VERSION 5.7 ;
  NOWIREEXTENSIONATPIN ON ;
  DIVIDERCHAR "/" ;
  BUSBITCHARS "[]" ;
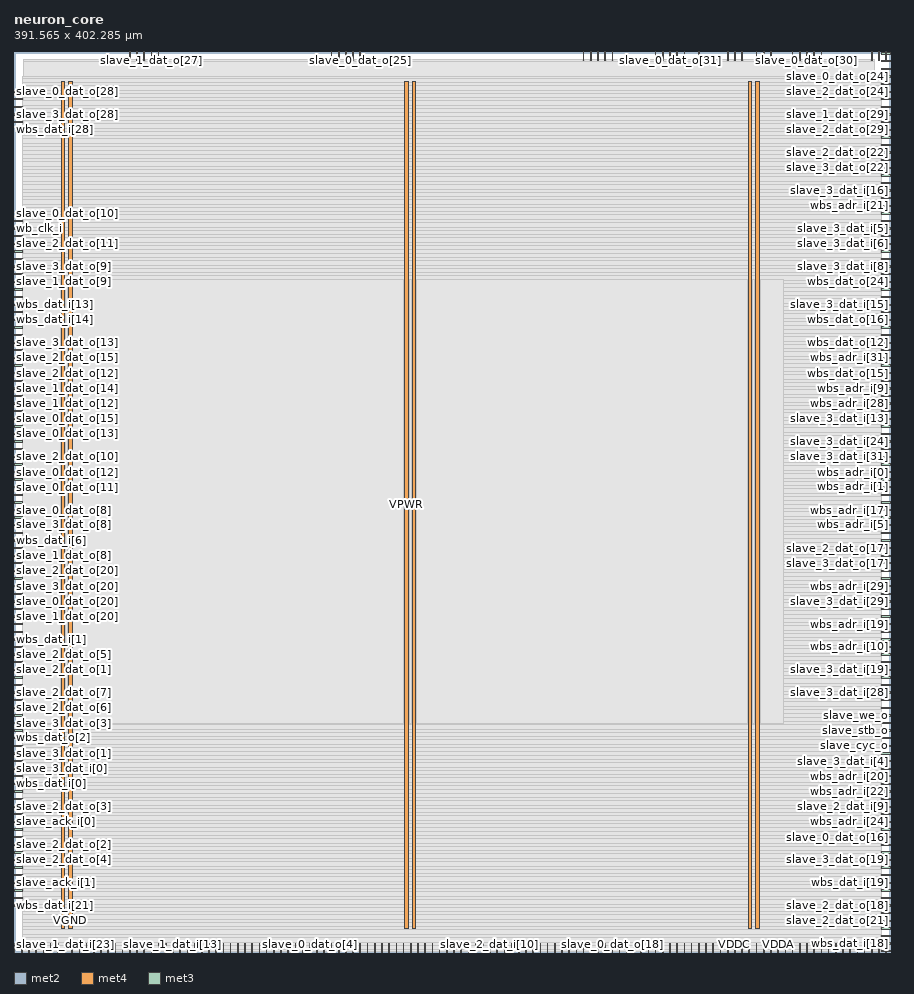
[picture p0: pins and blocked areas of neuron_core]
MACRO neuron_core
  CLASS BLOCK ;
  FOREIGN neuron_core ;
  ORIGIN 0.000 0.000 ;
  SIZE 391.565 BY 402.285 ;
  PIN VDDA
    DIRECTION INOUT ;
    USE SIGNAL ;
    PORT
      LAYER met2 ;
        RECT 341.410 0.000 341.690 4.000 ;
    END
  END VDDA
  PIN VDDC
    DIRECTION INOUT ;
    USE SIGNAL ;
    PORT
      LAYER met2 ;
        RECT 322.090 0.000 322.370 4.000 ;
    END
  END VDDC
  PIN VGND
    DIRECTION INOUT ;
    USE GROUND ;
    PORT
      LAYER met4 ;
        RECT 24.340 10.640 25.940 389.200 ;
    END
    PORT
      LAYER met4 ;
        RECT 177.940 10.640 179.540 389.200 ;
    END
    PORT
      LAYER met4 ;
        RECT 331.540 10.640 333.140 389.200 ;
    END
  END VGND
  PIN VPWR
    DIRECTION INOUT ;
    USE POWER ;
    PORT
      LAYER met4 ;
        RECT 21.040 10.640 22.640 389.200 ;
    END
    PORT
      LAYER met4 ;
        RECT 174.640 10.640 176.240 389.200 ;
    END
    PORT
      LAYER met4 ;
        RECT 328.240 10.640 329.840 389.200 ;
    END
  END VPWR
  PIN VSS
    DIRECTION INOUT ;
    USE SIGNAL ;
    PORT
      LAYER met2 ;
        RECT 19.410 0.000 19.690 4.000 ;
    END
  END VSS
  PIN slave_0_dat_i[0]
    DIRECTION INPUT ;
    USE SIGNAL ;
    ANTENNAGATEAREA 0.631200 ;
    ANTENNADIFFAREA 0.434700 ;
    PORT
      LAYER met2 ;
        RECT 167.530 0.000 167.810 4.000 ;
    END
  END slave_0_dat_i[0]
  PIN slave_0_dat_i[10]
    DIRECTION INPUT ;
    USE SIGNAL ;
    PORT
      LAYER met2 ;
        RECT 312.430 0.000 312.710 4.000 ;
    END
  END slave_0_dat_i[10]
  PIN slave_0_dat_i[11]
    DIRECTION INPUT ;
    USE SIGNAL ;
    PORT
      LAYER met2 ;
        RECT 22.630 0.000 22.910 4.000 ;
    END
  END slave_0_dat_i[11]
  PIN slave_0_dat_i[12]
    DIRECTION INPUT ;
    USE SIGNAL ;
    PORT
      LAYER met2 ;
        RECT 74.150 0.000 74.430 4.000 ;
    END
  END slave_0_dat_i[12]
  PIN slave_0_dat_i[13]
    DIRECTION INPUT ;
    USE SIGNAL ;
    PORT
      LAYER met2 ;
        RECT 389.710 0.000 389.990 4.000 ;
    END
  END slave_0_dat_i[13]
  PIN slave_0_dat_i[14]
    DIRECTION INPUT ;
    USE SIGNAL ;
    PORT
      LAYER met2 ;
        RECT 54.830 0.000 55.110 4.000 ;
    END
  END slave_0_dat_i[14]
  PIN slave_0_dat_i[15]
    DIRECTION INPUT ;
    USE SIGNAL ;
    PORT
      LAYER met2 ;
        RECT 48.390 0.000 48.670 4.000 ;
    END
  END slave_0_dat_i[15]
  PIN slave_0_dat_i[16]
    DIRECTION INPUT ;
    USE SIGNAL ;
    PORT
      LAYER met2 ;
        RECT 96.690 0.000 96.970 4.000 ;
    END
  END slave_0_dat_i[16]
  PIN slave_0_dat_i[17]
    DIRECTION INPUT ;
    USE SIGNAL ;
    PORT
      LAYER met2 ;
        RECT 87.030 0.000 87.310 4.000 ;
    END
  END slave_0_dat_i[17]
  PIN slave_0_dat_i[18]
    DIRECTION INPUT ;
    USE SIGNAL ;
    PORT
      LAYER met2 ;
        RECT 64.490 0.000 64.770 4.000 ;
    END
  END slave_0_dat_i[18]
  PIN slave_0_dat_i[19]
    DIRECTION INPUT ;
    USE SIGNAL ;
    PORT
      LAYER met2 ;
        RECT 58.050 0.000 58.330 4.000 ;
    END
  END slave_0_dat_i[19]
  PIN slave_0_dat_i[1]
    DIRECTION INPUT ;
    USE SIGNAL ;
    PORT
      LAYER met2 ;
        RECT 45.170 0.000 45.450 4.000 ;
    END
  END slave_0_dat_i[1]
  PIN slave_0_dat_i[20]
    DIRECTION INPUT ;
    USE SIGNAL ;
    PORT
      LAYER met2 ;
        RECT 386.490 0.000 386.770 4.000 ;
    END
  END slave_0_dat_i[20]
  PIN slave_0_dat_i[21]
    DIRECTION INPUT ;
    USE SIGNAL ;
    PORT
      LAYER met2 ;
        RECT 51.610 0.000 51.890 4.000 ;
    END
  END slave_0_dat_i[21]
  PIN slave_0_dat_i[22]
    DIRECTION INPUT ;
    USE SIGNAL ;
    PORT
      LAYER met2 ;
        RECT 80.590 0.000 80.870 4.000 ;
    END
  END slave_0_dat_i[22]
  PIN slave_0_dat_i[23]
    DIRECTION INPUT ;
    USE SIGNAL ;
    PORT
      LAYER met2 ;
        RECT 9.750 0.000 10.030 4.000 ;
    END
  END slave_0_dat_i[23]
  PIN slave_0_dat_i[24]
    DIRECTION INPUT ;
    USE SIGNAL ;
    PORT
      LAYER met2 ;
        RECT 183.630 0.000 183.910 4.000 ;
    END
  END slave_0_dat_i[24]
  PIN slave_0_dat_i[25]
    DIRECTION INPUT ;
    USE SIGNAL ;
    PORT
      LAYER met2 ;
        RECT 83.810 0.000 84.090 4.000 ;
    END
  END slave_0_dat_i[25]
  PIN slave_0_dat_i[26]
    DIRECTION INPUT ;
    USE SIGNAL ;
    PORT
      LAYER met2 ;
        RECT 103.130 0.000 103.410 4.000 ;
    END
  END slave_0_dat_i[26]
  PIN slave_0_dat_i[27]
    DIRECTION INPUT ;
    USE SIGNAL ;
    PORT
      LAYER met2 ;
        RECT 370.390 0.000 370.670 4.000 ;
    END
  END slave_0_dat_i[27]
  PIN slave_0_dat_i[28]
    DIRECTION INPUT ;
    USE SIGNAL ;
    PORT
      LAYER met2 ;
        RECT 206.170 0.000 206.450 4.000 ;
    END
  END slave_0_dat_i[28]
  PIN slave_0_dat_i[29]
    DIRECTION INPUT ;
    USE SIGNAL ;
    PORT
      LAYER met2 ;
        RECT 225.490 0.000 225.770 4.000 ;
    END
  END slave_0_dat_i[29]
  PIN slave_0_dat_i[2]
    DIRECTION INPUT ;
    USE SIGNAL ;
    PORT
      LAYER met2 ;
        RECT 90.250 0.000 90.530 4.000 ;
    END
  END slave_0_dat_i[2]
  PIN slave_0_dat_i[30]
    DIRECTION INPUT ;
    USE SIGNAL ;
    PORT
      LAYER met2 ;
        RECT 12.970 0.000 13.250 4.000 ;
    END
  END slave_0_dat_i[30]
  PIN slave_0_dat_i[31]
    DIRECTION INPUT ;
    USE SIGNAL ;
    PORT
      LAYER met2 ;
        RECT 93.470 0.000 93.750 4.000 ;
    END
  END slave_0_dat_i[31]
  PIN slave_0_dat_i[3]
    DIRECTION INPUT ;
    USE SIGNAL ;
    PORT
      LAYER met2 ;
        RECT 106.350 0.000 106.630 4.000 ;
    END
  END slave_0_dat_i[3]
  PIN slave_0_dat_i[4]
    DIRECTION INPUT ;
    USE SIGNAL ;
    PORT
      LAYER met2 ;
        RECT 347.850 0.000 348.130 4.000 ;
    END
  END slave_0_dat_i[4]
  PIN slave_0_dat_i[5]
    DIRECTION INPUT ;
    USE SIGNAL ;
    PORT
      LAYER met2 ;
        RECT 202.950 0.000 203.230 4.000 ;
    END
  END slave_0_dat_i[5]
  PIN slave_0_dat_i[6]
    DIRECTION INPUT ;
    USE SIGNAL ;
    PORT
      LAYER met2 ;
        RECT 99.910 0.000 100.190 4.000 ;
    END
  END slave_0_dat_i[6]
  PIN slave_0_dat_i[7]
    DIRECTION INPUT ;
    USE SIGNAL ;
    PORT
      LAYER met2 ;
        RECT 41.950 0.000 42.230 4.000 ;
    END
  END slave_0_dat_i[7]
  PIN slave_0_dat_i[8]
    DIRECTION INPUT ;
    USE SIGNAL ;
    PORT
      LAYER met2 ;
        RECT 190.070 0.000 190.350 4.000 ;
    END
  END slave_0_dat_i[8]
  PIN slave_0_dat_i[9]
    DIRECTION INPUT ;
    USE SIGNAL ;
    PORT
      LAYER met2 ;
        RECT 3.310 0.000 3.590 4.000 ;
    END
  END slave_0_dat_i[9]
  PIN slave_0_dat_o[0]
    DIRECTION OUTPUT ;
    USE SIGNAL ;
    ANTENNADIFFAREA 0.445500 ;
    PORT
      LAYER met2 ;
        RECT 109.570 0.000 109.850 4.000 ;
    END
  END slave_0_dat_o[0]
  PIN slave_0_dat_o[10]
    DIRECTION OUTPUT ;
    USE SIGNAL ;
    ANTENNADIFFAREA 0.445500 ;
    PORT
      LAYER met3 ;
        RECT 0.000 326.440 4.000 327.040 ;
    END
  END slave_0_dat_o[10]
  PIN slave_0_dat_o[11]
    DIRECTION OUTPUT ;
    USE SIGNAL ;
    ANTENNADIFFAREA 0.445500 ;
    PORT
      LAYER met3 ;
        RECT 0.000 207.440 4.000 208.040 ;
    END
  END slave_0_dat_o[11]
  PIN slave_0_dat_o[12]
    DIRECTION OUTPUT ;
    USE SIGNAL ;
    ANTENNADIFFAREA 0.445500 ;
    PORT
      LAYER met3 ;
        RECT 0.000 214.240 4.000 214.840 ;
    END
  END slave_0_dat_o[12]
  PIN slave_0_dat_o[13]
    DIRECTION OUTPUT ;
    USE SIGNAL ;
    ANTENNADIFFAREA 0.445500 ;
    PORT
      LAYER met3 ;
        RECT 0.000 231.240 4.000 231.840 ;
    END
  END slave_0_dat_o[13]
  PIN slave_0_dat_o[14]
    DIRECTION OUTPUT ;
    USE SIGNAL ;
    ANTENNADIFFAREA 0.445500 ;
    PORT
      LAYER met3 ;
        RECT 0.000 234.640 4.000 235.240 ;
    END
  END slave_0_dat_o[14]
  PIN slave_0_dat_o[15]
    DIRECTION OUTPUT ;
    USE SIGNAL ;
    ANTENNADIFFAREA 0.445500 ;
    PORT
      LAYER met3 ;
        RECT 0.000 238.040 4.000 238.640 ;
    END
  END slave_0_dat_o[15]
  PIN slave_0_dat_o[16]
    DIRECTION OUTPUT ;
    USE SIGNAL ;
    ANTENNADIFFAREA 0.445500 ;
    PORT
      LAYER met3 ;
        RECT 387.565 51.040 391.565 51.640 ;
    END
  END slave_0_dat_o[16]
  PIN slave_0_dat_o[17]
    DIRECTION OUTPUT ;
    USE SIGNAL ;
    ANTENNADIFFAREA 0.445500 ;
    PORT
      LAYER met3 ;
        RECT 387.565 166.640 391.565 167.240 ;
    END
  END slave_0_dat_o[17]
  PIN slave_0_dat_o[18]
    DIRECTION OUTPUT ;
    USE SIGNAL ;
    ANTENNADIFFAREA 0.445500 ;
    PORT
      LAYER met2 ;
        RECT 267.350 0.000 267.630 4.000 ;
    END
  END slave_0_dat_o[18]
  PIN slave_0_dat_o[19]
    DIRECTION OUTPUT ;
    USE SIGNAL ;
    ANTENNADIFFAREA 0.445500 ;
    PORT
      LAYER met2 ;
        RECT 357.510 0.000 357.790 4.000 ;
    END
  END slave_0_dat_o[19]
  PIN slave_0_dat_o[1]
    DIRECTION OUTPUT ;
    USE SIGNAL ;
    ANTENNADIFFAREA 0.445500 ;
    PORT
      LAYER met2 ;
        RECT 116.010 0.000 116.290 4.000 ;
    END
  END slave_0_dat_o[1]
  PIN slave_0_dat_o[20]
    DIRECTION OUTPUT ;
    USE SIGNAL ;
    ANTENNADIFFAREA 0.445500 ;
    PORT
      LAYER met3 ;
        RECT 0.000 156.440 4.000 157.040 ;
    END
  END slave_0_dat_o[20]
  PIN slave_0_dat_o[21]
    DIRECTION OUTPUT ;
    USE SIGNAL ;
    ANTENNADIFFAREA 0.445500 ;
    PORT
      LAYER met2 ;
        RECT 193.290 0.000 193.570 4.000 ;
    END
  END slave_0_dat_o[21]
  PIN slave_0_dat_o[22]
    DIRECTION OUTPUT ;
    USE SIGNAL ;
    ANTENNADIFFAREA 0.445500 ;
    PORT
      LAYER met3 ;
        RECT 387.565 343.440 391.565 344.040 ;
    END
  END slave_0_dat_o[22]
  PIN slave_0_dat_o[23]
    DIRECTION OUTPUT ;
    USE SIGNAL ;
    ANTENNADIFFAREA 0.445500 ;
    PORT
      LAYER met2 ;
        RECT 254.470 398.285 254.750 402.285 ;
    END
  END slave_0_dat_o[23]
  PIN slave_0_dat_o[24]
    DIRECTION OUTPUT ;
    USE SIGNAL ;
    ANTENNADIFFAREA 0.445500 ;
    PORT
      LAYER met3 ;
        RECT 387.565 391.040 391.565 391.640 ;
    END
  END slave_0_dat_o[24]
  PIN slave_0_dat_o[25]
    DIRECTION OUTPUT ;
    USE SIGNAL ;
    ANTENNADIFFAREA 0.445500 ;
    PORT
      LAYER met2 ;
        RECT 154.650 398.285 154.930 402.285 ;
    END
  END slave_0_dat_o[25]
  PIN slave_0_dat_o[26]
    DIRECTION OUTPUT ;
    USE SIGNAL ;
    ANTENNADIFFAREA 0.445500 ;
    PORT
      LAYER met2 ;
        RECT 293.110 0.000 293.390 4.000 ;
    END
  END slave_0_dat_o[26]
  PIN slave_0_dat_o[27]
    DIRECTION OUTPUT ;
    USE SIGNAL ;
    ANTENNADIFFAREA 0.445500 ;
    PORT
      LAYER met2 ;
        RECT 51.610 398.285 51.890 402.285 ;
    END
  END slave_0_dat_o[27]
  PIN slave_0_dat_o[28]
    DIRECTION OUTPUT ;
    USE SIGNAL ;
    ANTENNADIFFAREA 0.445500 ;
    PORT
      LAYER met3 ;
        RECT 0.000 384.240 4.000 384.840 ;
    END
  END slave_0_dat_o[28]
  PIN slave_0_dat_o[29]
    DIRECTION OUTPUT ;
    USE SIGNAL ;
    ANTENNADIFFAREA 0.445500 ;
    PORT
      LAYER met3 ;
        RECT 387.565 363.840 391.565 364.440 ;
    END
  END slave_0_dat_o[29]
  PIN slave_0_dat_o[2]
    DIRECTION OUTPUT ;
    USE SIGNAL ;
    ANTENNADIFFAREA 0.445500 ;
    PORT
      LAYER met2 ;
        RECT 119.230 0.000 119.510 4.000 ;
    END
  END slave_0_dat_o[2]
  PIN slave_0_dat_o[30]
    DIRECTION OUTPUT ;
    USE SIGNAL ;
    ANTENNADIFFAREA 0.445500 ;
    PORT
      LAYER met2 ;
        RECT 354.290 398.285 354.570 402.285 ;
    END
  END slave_0_dat_o[30]
  PIN slave_0_dat_o[31]
    DIRECTION OUTPUT ;
    USE SIGNAL ;
    ANTENNADIFFAREA 0.445500 ;
    PORT
      LAYER met2 ;
        RECT 293.110 398.285 293.390 402.285 ;
    END
  END slave_0_dat_o[31]
  PIN slave_0_dat_o[3]
    DIRECTION OUTPUT ;
    USE SIGNAL ;
    ANTENNADIFFAREA 0.445500 ;
    PORT
      LAYER met2 ;
        RECT 125.670 0.000 125.950 4.000 ;
    END
  END slave_0_dat_o[3]
  PIN slave_0_dat_o[4]
    DIRECTION OUTPUT ;
    USE SIGNAL ;
    ANTENNADIFFAREA 0.445500 ;
    PORT
      LAYER met2 ;
        RECT 132.110 0.000 132.390 4.000 ;
    END
  END slave_0_dat_o[4]
  PIN slave_0_dat_o[5]
    DIRECTION OUTPUT ;
    USE SIGNAL ;
    ANTENNADIFFAREA 0.445500 ;
    PORT
      LAYER met2 ;
        RECT 128.890 0.000 129.170 4.000 ;
    END
  END slave_0_dat_o[5]
  PIN slave_0_dat_o[6]
    DIRECTION OUTPUT ;
    USE SIGNAL ;
    ANTENNADIFFAREA 0.445500 ;
    PORT
      LAYER met2 ;
        RECT 122.450 0.000 122.730 4.000 ;
    END
  END slave_0_dat_o[6]
  PIN slave_0_dat_o[7]
    DIRECTION OUTPUT ;
    USE SIGNAL ;
    ANTENNADIFFAREA 0.445500 ;
    PORT
      LAYER met2 ;
        RECT 112.790 0.000 113.070 4.000 ;
    END
  END slave_0_dat_o[7]
  PIN slave_0_dat_o[8]
    DIRECTION OUTPUT ;
    USE SIGNAL ;
    ANTENNADIFFAREA 0.445500 ;
    PORT
      LAYER met3 ;
        RECT 0.000 197.240 4.000 197.840 ;
    END
  END slave_0_dat_o[8]
  PIN slave_0_dat_o[9]
    DIRECTION OUTPUT ;
    USE SIGNAL ;
    ANTENNADIFFAREA 0.445500 ;
    PORT
      LAYER met3 ;
        RECT 0.000 295.840 4.000 296.440 ;
    END
  END slave_0_dat_o[9]
  PIN slave_1_dat_i[0]
    DIRECTION INPUT ;
    USE SIGNAL ;
    ANTENNAGATEAREA 0.631200 ;
    ANTENNADIFFAREA 0.434700 ;
    PORT
      LAYER met2 ;
        RECT 173.970 0.000 174.250 4.000 ;
    END
  END slave_1_dat_i[0]
  PIN slave_1_dat_i[10]
    DIRECTION INPUT ;
    USE SIGNAL ;
    PORT
      LAYER met2 ;
        RECT 180.410 0.000 180.690 4.000 ;
    END
  END slave_1_dat_i[10]
  PIN slave_1_dat_i[11]
    DIRECTION INPUT ;
    USE SIGNAL ;
    PORT
      LAYER met2 ;
        RECT 6.530 0.000 6.810 4.000 ;
    END
  END slave_1_dat_i[11]
  PIN slave_1_dat_i[12]
    DIRECTION INPUT ;
    USE SIGNAL ;
    PORT
      LAYER met2 ;
        RECT 222.270 0.000 222.550 4.000 ;
    END
  END slave_1_dat_i[12]
  PIN slave_1_dat_i[13]
    DIRECTION INPUT ;
    USE SIGNAL ;
    PORT
      LAYER met2 ;
        RECT 70.930 0.000 71.210 4.000 ;
    END
  END slave_1_dat_i[13]
  PIN slave_1_dat_i[14]
    DIRECTION INPUT ;
    USE SIGNAL ;
    PORT
      LAYER met2 ;
        RECT 228.710 0.000 228.990 4.000 ;
    END
  END slave_1_dat_i[14]
  PIN slave_1_dat_i[15]
    DIRECTION INPUT ;
    USE SIGNAL ;
    PORT
      LAYER met2 ;
        RECT 35.510 0.000 35.790 4.000 ;
    END
  END slave_1_dat_i[15]
  PIN slave_1_dat_i[16]
    DIRECTION INPUT ;
    USE SIGNAL ;
    PORT
      LAYER met2 ;
        RECT 383.270 0.000 383.550 4.000 ;
    END
  END slave_1_dat_i[16]
  PIN slave_1_dat_i[17]
    DIRECTION INPUT ;
    USE SIGNAL ;
    PORT
      LAYER met2 ;
        RECT 25.850 0.000 26.130 4.000 ;
    END
  END slave_1_dat_i[17]
  PIN slave_1_dat_i[18]
    DIRECTION INPUT ;
    USE SIGNAL ;
    PORT
      LAYER met2 ;
        RECT 67.710 0.000 67.990 4.000 ;
    END
  END slave_1_dat_i[18]
  PIN slave_1_dat_i[19]
    DIRECTION INPUT ;
    USE SIGNAL ;
    PORT
      LAYER met2 ;
        RECT 161.090 0.000 161.370 4.000 ;
    END
  END slave_1_dat_i[19]
  PIN slave_1_dat_i[1]
    DIRECTION INPUT ;
    USE SIGNAL ;
    PORT
      LAYER met2 ;
        RECT 186.850 0.000 187.130 4.000 ;
    END
  END slave_1_dat_i[1]
  PIN slave_1_dat_i[20]
    DIRECTION INPUT ;
    USE SIGNAL ;
    PORT
      LAYER met2 ;
        RECT 373.610 0.000 373.890 4.000 ;
    END
  END slave_1_dat_i[20]
  PIN slave_1_dat_i[21]
    DIRECTION INPUT ;
    USE SIGNAL ;
    PORT
      LAYER met2 ;
        RECT 215.830 0.000 216.110 4.000 ;
    END
  END slave_1_dat_i[21]
  PIN slave_1_dat_i[22]
    DIRECTION INPUT ;
    USE SIGNAL ;
    PORT
      LAYER met2 ;
        RECT 32.290 0.000 32.570 4.000 ;
    END
  END slave_1_dat_i[22]
  PIN slave_1_dat_i[23]
    DIRECTION INPUT ;
    USE SIGNAL ;
    PORT
      LAYER met2 ;
        RECT 16.190 0.000 16.470 4.000 ;
    END
  END slave_1_dat_i[23]
  PIN slave_1_dat_i[24]
    DIRECTION INPUT ;
    USE SIGNAL ;
    PORT
      LAYER met2 ;
        RECT 231.930 0.000 232.210 4.000 ;
    END
  END slave_1_dat_i[24]
  PIN slave_1_dat_i[25]
    DIRECTION INPUT ;
    USE SIGNAL ;
    PORT
      LAYER met2 ;
        RECT 164.310 0.000 164.590 4.000 ;
    END
  END slave_1_dat_i[25]
  PIN slave_1_dat_i[26]
    DIRECTION INPUT ;
    USE SIGNAL ;
    PORT
      LAYER met2 ;
        RECT 0.090 0.000 0.370 4.000 ;
    END
  END slave_1_dat_i[26]
  PIN slave_1_dat_i[27]
    DIRECTION INPUT ;
    USE SIGNAL ;
    PORT
      LAYER met2 ;
        RECT 38.730 0.000 39.010 4.000 ;
    END
  END slave_1_dat_i[27]
  PIN slave_1_dat_i[28]
    DIRECTION INPUT ;
    USE SIGNAL ;
    PORT
      LAYER met2 ;
        RECT 61.270 0.000 61.550 4.000 ;
    END
  END slave_1_dat_i[28]
  PIN slave_1_dat_i[29]
    DIRECTION INPUT ;
    USE SIGNAL ;
    PORT
      LAYER met2 ;
        RECT 177.190 0.000 177.470 4.000 ;
    END
  END slave_1_dat_i[29]
  PIN slave_1_dat_i[2]
    DIRECTION INPUT ;
    USE SIGNAL ;
    PORT
      LAYER met2 ;
        RECT 286.670 0.000 286.950 4.000 ;
    END
  END slave_1_dat_i[2]
  PIN slave_1_dat_i[30]
    DIRECTION INPUT ;
    USE SIGNAL ;
    PORT
      LAYER met2 ;
        RECT 305.990 0.000 306.270 4.000 ;
    END
  END slave_1_dat_i[30]
  PIN slave_1_dat_i[31]
    DIRECTION INPUT ;
    USE SIGNAL ;
    PORT
      LAYER met2 ;
        RECT 257.690 0.000 257.970 4.000 ;
    END
  END slave_1_dat_i[31]
  PIN slave_1_dat_i[3]
    DIRECTION INPUT ;
    USE SIGNAL ;
    PORT
      LAYER met2 ;
        RECT 277.010 0.000 277.290 4.000 ;
    END
  END slave_1_dat_i[3]
  PIN slave_1_dat_i[4]
    DIRECTION INPUT ;
    USE SIGNAL ;
    PORT
      LAYER met2 ;
        RECT 29.070 0.000 29.350 4.000 ;
    END
  END slave_1_dat_i[4]
  PIN slave_1_dat_i[5]
    DIRECTION INPUT ;
    USE SIGNAL ;
    PORT
      LAYER met2 ;
        RECT 77.370 0.000 77.650 4.000 ;
    END
  END slave_1_dat_i[5]
  PIN slave_1_dat_i[6]
    DIRECTION INPUT ;
    USE SIGNAL ;
    PORT
      LAYER met2 ;
        RECT 199.730 0.000 200.010 4.000 ;
    END
  END slave_1_dat_i[6]
  PIN slave_1_dat_i[7]
    DIRECTION INPUT ;
    USE SIGNAL ;
    PORT
      LAYER met2 ;
        RECT 354.290 0.000 354.570 4.000 ;
    END
  END slave_1_dat_i[7]
  PIN slave_1_dat_i[8]
    DIRECTION INPUT ;
    USE SIGNAL ;
    PORT
      LAYER met2 ;
        RECT 344.630 0.000 344.910 4.000 ;
    END
  END slave_1_dat_i[8]
  PIN slave_1_dat_i[9]
    DIRECTION INPUT ;
    USE SIGNAL ;
    PORT
      LAYER met2 ;
        RECT 209.390 0.000 209.670 4.000 ;
    END
  END slave_1_dat_i[9]
  PIN slave_1_dat_o[0]
    DIRECTION OUTPUT ;
    USE SIGNAL ;
    ANTENNADIFFAREA 0.445500 ;
    PORT
      LAYER met2 ;
        RECT 157.870 0.000 158.150 4.000 ;
    END
  END slave_1_dat_o[0]
  PIN slave_1_dat_o[10]
    DIRECTION OUTPUT ;
    USE SIGNAL ;
    ANTENNADIFFAREA 0.445500 ;
    PORT
      LAYER met3 ;
        RECT 0.000 217.640 4.000 218.240 ;
    END
  END slave_1_dat_o[10]
  PIN slave_1_dat_o[11]
    DIRECTION OUTPUT ;
    USE SIGNAL ;
    ANTENNADIFFAREA 0.445500 ;
    PORT
      LAYER met3 ;
        RECT 0.000 312.840 4.000 313.440 ;
    END
  END slave_1_dat_o[11]
  PIN slave_1_dat_o[12]
    DIRECTION OUTPUT ;
    USE SIGNAL ;
    ANTENNADIFFAREA 0.445500 ;
    PORT
      LAYER met3 ;
        RECT 0.000 241.440 4.000 242.040 ;
    END
  END slave_1_dat_o[12]
  PIN slave_1_dat_o[13]
    DIRECTION OUTPUT ;
    USE SIGNAL ;
    ANTENNADIFFAREA 0.445500 ;
    PORT
      LAYER met3 ;
        RECT 0.000 244.840 4.000 245.440 ;
    END
  END slave_1_dat_o[13]
  PIN slave_1_dat_o[14]
    DIRECTION OUTPUT ;
    USE SIGNAL ;
    ANTENNADIFFAREA 0.445500 ;
    PORT
      LAYER met3 ;
        RECT 0.000 248.240 4.000 248.840 ;
    END
  END slave_1_dat_o[14]
  PIN slave_1_dat_o[15]
    DIRECTION OUTPUT ;
    USE SIGNAL ;
    ANTENNADIFFAREA 0.445500 ;
    PORT
      LAYER met3 ;
        RECT 0.000 251.640 4.000 252.240 ;
    END
  END slave_1_dat_o[15]
  PIN slave_1_dat_o[16]
    DIRECTION OUTPUT ;
    USE SIGNAL ;
    ANTENNADIFFAREA 0.445500 ;
    PORT
      LAYER met3 ;
        RECT 387.565 34.040 391.565 34.640 ;
    END
  END slave_1_dat_o[16]
  PIN slave_1_dat_o[17]
    DIRECTION OUTPUT ;
    USE SIGNAL ;
    ANTENNADIFFAREA 0.445500 ;
    PORT
      LAYER met3 ;
        RECT 387.565 183.640 391.565 184.240 ;
    END
  END slave_1_dat_o[17]
  PIN slave_1_dat_o[18]
    DIRECTION OUTPUT ;
    USE SIGNAL ;
    ANTENNADIFFAREA 0.445500 ;
    PORT
      LAYER met2 ;
        RECT 270.570 0.000 270.850 4.000 ;
    END
  END slave_1_dat_o[18]
  PIN slave_1_dat_o[19]
    DIRECTION OUTPUT ;
    USE SIGNAL ;
    ANTENNADIFFAREA 0.445500 ;
    PORT
      LAYER met2 ;
        RECT 360.730 0.000 361.010 4.000 ;
    END
  END slave_1_dat_o[19]
  PIN slave_1_dat_o[1]
    DIRECTION OUTPUT ;
    USE SIGNAL ;
    ANTENNADIFFAREA 0.445500 ;
    PORT
      LAYER met2 ;
        RECT 151.430 0.000 151.710 4.000 ;
    END
  END slave_1_dat_o[1]
  PIN slave_1_dat_o[20]
    DIRECTION OUTPUT ;
    USE SIGNAL ;
    ANTENNADIFFAREA 0.445500 ;
    PORT
      LAYER met3 ;
        RECT 0.000 153.040 4.000 153.640 ;
    END
  END slave_1_dat_o[20]
  PIN slave_1_dat_o[21]
    DIRECTION OUTPUT ;
    USE SIGNAL ;
    ANTENNADIFFAREA 0.445500 ;
    PORT
      LAYER met2 ;
        RECT 196.510 0.000 196.790 4.000 ;
    END
  END slave_1_dat_o[21]
  PIN slave_1_dat_o[22]
    DIRECTION OUTPUT ;
    USE SIGNAL ;
    ANTENNADIFFAREA 0.445500 ;
    PORT
      LAYER met3 ;
        RECT 387.565 353.640 391.565 354.240 ;
    END
  END slave_1_dat_o[22]
  PIN slave_1_dat_o[23]
    DIRECTION OUTPUT ;
    USE SIGNAL ;
    ANTENNADIFFAREA 0.445500 ;
    PORT
      LAYER met2 ;
        RECT 267.350 398.285 267.630 402.285 ;
    END
  END slave_1_dat_o[23]
  PIN slave_1_dat_o[24]
    DIRECTION OUTPUT ;
    USE SIGNAL ;
    ANTENNADIFFAREA 0.445500 ;
    PORT
      LAYER met3 ;
        RECT 387.565 380.840 391.565 381.440 ;
    END
  END slave_1_dat_o[24]
  PIN slave_1_dat_o[25]
    DIRECTION OUTPUT ;
    USE SIGNAL ;
    ANTENNADIFFAREA 0.445500 ;
    PORT
      LAYER met2 ;
        RECT 148.210 398.285 148.490 402.285 ;
    END
  END slave_1_dat_o[25]
  PIN slave_1_dat_o[26]
    DIRECTION OUTPUT ;
    USE SIGNAL ;
    ANTENNADIFFAREA 0.445500 ;
    PORT
      LAYER met2 ;
        RECT 296.330 0.000 296.610 4.000 ;
    END
  END slave_1_dat_o[26]
  PIN slave_1_dat_o[27]
    DIRECTION OUTPUT ;
    USE SIGNAL ;
    ANTENNADIFFAREA 0.445500 ;
    PORT
      LAYER met2 ;
        RECT 61.270 398.285 61.550 402.285 ;
    END
  END slave_1_dat_o[27]
  PIN slave_1_dat_o[28]
    DIRECTION OUTPUT ;
    USE SIGNAL ;
    ANTENNADIFFAREA 0.445500 ;
    PORT
      LAYER met3 ;
        RECT 0.000 377.440 4.000 378.040 ;
    END
  END slave_1_dat_o[28]
  PIN slave_1_dat_o[29]
    DIRECTION OUTPUT ;
    USE SIGNAL ;
    ANTENNADIFFAREA 0.445500 ;
    PORT
      LAYER met3 ;
        RECT 387.565 374.040 391.565 374.640 ;
    END
  END slave_1_dat_o[29]
  PIN slave_1_dat_o[2]
    DIRECTION OUTPUT ;
    USE SIGNAL ;
    ANTENNADIFFAREA 0.445500 ;
    PORT
      LAYER met2 ;
        RECT 141.770 0.000 142.050 4.000 ;
    END
  END slave_1_dat_o[2]
  PIN slave_1_dat_o[30]
    DIRECTION OUTPUT ;
    USE SIGNAL ;
    ANTENNADIFFAREA 0.445500 ;
    PORT
      LAYER met2 ;
        RECT 347.850 398.285 348.130 402.285 ;
    END
  END slave_1_dat_o[30]
  PIN slave_1_dat_o[31]
    DIRECTION OUTPUT ;
    USE SIGNAL ;
    ANTENNADIFFAREA 0.445500 ;
    PORT
      LAYER met2 ;
        RECT 286.670 398.285 286.950 402.285 ;
    END
  END slave_1_dat_o[31]
  PIN slave_1_dat_o[3]
    DIRECTION OUTPUT ;
    USE SIGNAL ;
    ANTENNADIFFAREA 0.445500 ;
    PORT
      LAYER met2 ;
        RECT 138.550 0.000 138.830 4.000 ;
    END
  END slave_1_dat_o[3]
  PIN slave_1_dat_o[4]
    DIRECTION OUTPUT ;
    USE SIGNAL ;
    ANTENNADIFFAREA 0.445500 ;
    PORT
      LAYER met2 ;
        RECT 144.990 0.000 145.270 4.000 ;
    END
  END slave_1_dat_o[4]
  PIN slave_1_dat_o[5]
    DIRECTION OUTPUT ;
    USE SIGNAL ;
    ANTENNADIFFAREA 0.445500 ;
    PORT
      LAYER met2 ;
        RECT 154.650 0.000 154.930 4.000 ;
    END
  END slave_1_dat_o[5]
  PIN slave_1_dat_o[6]
    DIRECTION OUTPUT ;
    USE SIGNAL ;
    ANTENNADIFFAREA 0.445500 ;
    PORT
      LAYER met2 ;
        RECT 148.210 0.000 148.490 4.000 ;
    END
  END slave_1_dat_o[6]
  PIN slave_1_dat_o[7]
    DIRECTION OUTPUT ;
    USE SIGNAL ;
    ANTENNADIFFAREA 0.445500 ;
    PORT
      LAYER met2 ;
        RECT 135.330 0.000 135.610 4.000 ;
    END
  END slave_1_dat_o[7]
  PIN slave_1_dat_o[8]
    DIRECTION OUTPUT ;
    USE SIGNAL ;
    ANTENNADIFFAREA 0.445500 ;
    PORT
      LAYER met3 ;
        RECT 0.000 176.840 4.000 177.440 ;
    END
  END slave_1_dat_o[8]
  PIN slave_1_dat_o[9]
    DIRECTION OUTPUT ;
    USE SIGNAL ;
    ANTENNADIFFAREA 0.445500 ;
    PORT
      LAYER met3 ;
        RECT 0.000 299.240 4.000 299.840 ;
    END
  END slave_1_dat_o[9]
  PIN slave_2_dat_i[0]
    DIRECTION INPUT ;
    USE SIGNAL ;
    ANTENNAGATEAREA 0.560700 ;
    ANTENNADIFFAREA 0.434700 ;
    PORT
      LAYER met2 ;
        RECT 170.750 0.000 171.030 4.000 ;
    END
  END slave_2_dat_i[0]
  PIN slave_2_dat_i[10]
    DIRECTION INPUT ;
    USE SIGNAL ;
    PORT
      LAYER met2 ;
        RECT 212.610 0.000 212.890 4.000 ;
    END
  END slave_2_dat_i[10]
  PIN slave_2_dat_i[11]
    DIRECTION INPUT ;
    USE SIGNAL ;
    PORT
      LAYER met2 ;
        RECT 273.790 0.000 274.070 4.000 ;
    END
  END slave_2_dat_i[11]
  PIN slave_2_dat_i[12]
    DIRECTION INPUT ;
    USE SIGNAL ;
    PORT
      LAYER met2 ;
        RECT 219.050 0.000 219.330 4.000 ;
    END
  END slave_2_dat_i[12]
  PIN slave_2_dat_i[13]
    DIRECTION INPUT ;
    USE SIGNAL ;
    PORT
      LAYER met2 ;
        RECT 315.650 0.000 315.930 4.000 ;
    END
  END slave_2_dat_i[13]
  PIN slave_2_dat_i[14]
    DIRECTION INPUT ;
    USE SIGNAL ;
    PORT
      LAYER met2 ;
        RECT 248.030 0.000 248.310 4.000 ;
    END
  END slave_2_dat_i[14]
  PIN slave_2_dat_i[15]
    DIRECTION INPUT ;
    USE SIGNAL ;
    PORT
      LAYER met2 ;
        RECT 338.190 0.000 338.470 4.000 ;
    END
  END slave_2_dat_i[15]
  PIN slave_2_dat_i[16]
    DIRECTION INPUT ;
    USE SIGNAL ;
    PORT
      LAYER met2 ;
        RECT 280.230 0.000 280.510 4.000 ;
    END
  END slave_2_dat_i[16]
  PIN slave_2_dat_i[17]
    DIRECTION INPUT ;
    USE SIGNAL ;
    PORT
      LAYER met2 ;
        RECT 235.150 0.000 235.430 4.000 ;
    END
  END slave_2_dat_i[17]
  PIN slave_2_dat_i[18]
    DIRECTION INPUT ;
    USE SIGNAL ;
    PORT
      LAYER met2 ;
        RECT 238.370 0.000 238.650 4.000 ;
    END
  END slave_2_dat_i[18]
  PIN slave_2_dat_i[19]
    DIRECTION INPUT ;
    USE SIGNAL ;
    PORT
      LAYER met2 ;
        RECT 241.590 0.000 241.870 4.000 ;
    END
  END slave_2_dat_i[19]
  PIN slave_2_dat_i[1]
    DIRECTION INPUT ;
    USE SIGNAL ;
    PORT
      LAYER met2 ;
        RECT 244.810 0.000 245.090 4.000 ;
    END
  END slave_2_dat_i[1]
  PIN slave_2_dat_i[20]
    DIRECTION INPUT ;
    USE SIGNAL ;
    PORT
      LAYER met2 ;
        RECT 367.170 0.000 367.450 4.000 ;
    END
  END slave_2_dat_i[20]
  PIN slave_2_dat_i[21]
    DIRECTION INPUT ;
    USE SIGNAL ;
    PORT
      LAYER met2 ;
        RECT 251.250 0.000 251.530 4.000 ;
    END
  END slave_2_dat_i[21]
  PIN slave_2_dat_i[22]
    DIRECTION INPUT ;
    USE SIGNAL ;
    PORT
      LAYER met2 ;
        RECT 254.470 0.000 254.750 4.000 ;
    END
  END slave_2_dat_i[22]
  PIN slave_2_dat_i[23]
    DIRECTION INPUT ;
    USE SIGNAL ;
    PORT
      LAYER met2 ;
        RECT 334.970 0.000 335.250 4.000 ;
    END
  END slave_2_dat_i[23]
  PIN slave_2_dat_i[24]
    DIRECTION INPUT ;
    USE SIGNAL ;
    PORT
      LAYER met2 ;
        RECT 260.910 0.000 261.190 4.000 ;
    END
  END slave_2_dat_i[24]
  PIN slave_2_dat_i[25]
    DIRECTION INPUT ;
    USE SIGNAL ;
    PORT
      LAYER met2 ;
        RECT 264.130 0.000 264.410 4.000 ;
    END
  END slave_2_dat_i[25]
  PIN slave_2_dat_i[26]
    DIRECTION INPUT ;
    USE SIGNAL ;
    PORT
      LAYER met2 ;
        RECT 331.750 0.000 332.030 4.000 ;
    END
  END slave_2_dat_i[26]
  PIN slave_2_dat_i[27]
    DIRECTION INPUT ;
    USE SIGNAL ;
    PORT
      LAYER met2 ;
        RECT 299.550 0.000 299.830 4.000 ;
    END
  END slave_2_dat_i[27]
  PIN slave_2_dat_i[28]
    DIRECTION INPUT ;
    USE SIGNAL ;
    PORT
      LAYER met2 ;
        RECT 283.450 0.000 283.730 4.000 ;
    END
  END slave_2_dat_i[28]
  PIN slave_2_dat_i[29]
    DIRECTION INPUT ;
    USE SIGNAL ;
    PORT
      LAYER met2 ;
        RECT 328.530 0.000 328.810 4.000 ;
    END
  END slave_2_dat_i[29]
  PIN slave_2_dat_i[2]
    DIRECTION INPUT ;
    USE SIGNAL ;
    PORT
      LAYER met2 ;
        RECT 363.950 0.000 364.230 4.000 ;
    END
  END slave_2_dat_i[2]
  PIN slave_2_dat_i[30]
    DIRECTION INPUT ;
    USE SIGNAL ;
    PORT
      LAYER met2 ;
        RECT 380.050 0.000 380.330 4.000 ;
    END
  END slave_2_dat_i[30]
  PIN slave_2_dat_i[31]
    DIRECTION INPUT ;
    USE SIGNAL ;
    PORT
      LAYER met2 ;
        RECT 376.830 0.000 377.110 4.000 ;
    END
  END slave_2_dat_i[31]
  PIN slave_2_dat_i[3]
    DIRECTION INPUT ;
    USE SIGNAL ;
    PORT
      LAYER met2 ;
        RECT 309.210 0.000 309.490 4.000 ;
    END
  END slave_2_dat_i[3]
  PIN slave_2_dat_i[4]
    DIRECTION INPUT ;
    USE SIGNAL ;
    PORT
      LAYER met2 ;
        RECT 289.890 0.000 290.170 4.000 ;
    END
  END slave_2_dat_i[4]
  PIN slave_2_dat_i[5]
    DIRECTION INPUT ;
    USE SIGNAL ;
    PORT
      LAYER met2 ;
        RECT 325.310 0.000 325.590 4.000 ;
    END
  END slave_2_dat_i[5]
  PIN slave_2_dat_i[6]
    DIRECTION INPUT ;
    USE SIGNAL ;
    PORT
      LAYER met2 ;
        RECT 318.870 0.000 319.150 4.000 ;
    END
  END slave_2_dat_i[6]
  PIN slave_2_dat_i[7]
    DIRECTION INPUT ;
    USE SIGNAL ;
    PORT
      LAYER met2 ;
        RECT 351.070 0.000 351.350 4.000 ;
    END
  END slave_2_dat_i[7]
  PIN slave_2_dat_i[8]
    DIRECTION INPUT ;
    USE SIGNAL ;
    PORT
      LAYER met2 ;
        RECT 302.770 0.000 303.050 4.000 ;
    END
  END slave_2_dat_i[8]
  PIN slave_2_dat_i[9]
    DIRECTION INPUT ;
    USE SIGNAL ;
    PORT
      LAYER met3 ;
        RECT 387.565 64.640 391.565 65.240 ;
    END
  END slave_2_dat_i[9]
  PIN slave_2_dat_o[0]
    DIRECTION OUTPUT ;
    USE SIGNAL ;
    ANTENNADIFFAREA 0.445500 ;
    PORT
      LAYER met3 ;
        RECT 0.000 23.840 4.000 24.440 ;
    END
  END slave_2_dat_o[0]
  PIN slave_2_dat_o[10]
    DIRECTION OUTPUT ;
    USE SIGNAL ;
    ANTENNADIFFAREA 0.445500 ;
    PORT
      LAYER met3 ;
        RECT 0.000 221.040 4.000 221.640 ;
    END
  END slave_2_dat_o[10]
  PIN slave_2_dat_o[11]
    DIRECTION OUTPUT ;
    USE SIGNAL ;
    ANTENNADIFFAREA 0.445500 ;
    PORT
      LAYER met3 ;
        RECT 0.000 316.240 4.000 316.840 ;
    END
  END slave_2_dat_o[11]
  PIN slave_2_dat_o[12]
    DIRECTION OUTPUT ;
    USE SIGNAL ;
    ANTENNADIFFAREA 0.445500 ;
    PORT
      LAYER met3 ;
        RECT 0.000 255.040 4.000 255.640 ;
    END
  END slave_2_dat_o[12]
  PIN slave_2_dat_o[13]
    DIRECTION OUTPUT ;
    USE SIGNAL ;
    ANTENNADIFFAREA 0.445500 ;
    PORT
      LAYER met3 ;
        RECT 0.000 258.440 4.000 259.040 ;
    END
  END slave_2_dat_o[13]
  PIN slave_2_dat_o[14]
    DIRECTION OUTPUT ;
    USE SIGNAL ;
    ANTENNADIFFAREA 0.445500 ;
    PORT
      LAYER met3 ;
        RECT 0.000 261.840 4.000 262.440 ;
    END
  END slave_2_dat_o[14]
  PIN slave_2_dat_o[15]
    DIRECTION OUTPUT ;
    USE SIGNAL ;
    ANTENNADIFFAREA 0.445500 ;
    PORT
      LAYER met3 ;
        RECT 0.000 265.240 4.000 265.840 ;
    END
  END slave_2_dat_o[15]
  PIN slave_2_dat_o[16]
    DIRECTION OUTPUT ;
    USE SIGNAL ;
    ANTENNADIFFAREA 0.445500 ;
    PORT
      LAYER met3 ;
        RECT 387.565 47.640 391.565 48.240 ;
    END
  END slave_2_dat_o[16]
  PIN slave_2_dat_o[17]
    DIRECTION OUTPUT ;
    USE SIGNAL ;
    ANTENNADIFFAREA 0.445500 ;
    PORT
      LAYER met3 ;
        RECT 387.565 180.240 391.565 180.840 ;
    END
  END slave_2_dat_o[17]
  PIN slave_2_dat_o[18]
    DIRECTION OUTPUT ;
    USE SIGNAL ;
    ANTENNADIFFAREA 0.445500 ;
    PORT
      LAYER met3 ;
        RECT 387.565 20.440 391.565 21.040 ;
    END
  END slave_2_dat_o[18]
  PIN slave_2_dat_o[19]
    DIRECTION OUTPUT ;
    USE SIGNAL ;
    ANTENNADIFFAREA 0.445500 ;
    PORT
      LAYER met3 ;
        RECT 387.565 27.240 391.565 27.840 ;
    END
  END slave_2_dat_o[19]
  PIN slave_2_dat_o[1]
    DIRECTION OUTPUT ;
    USE SIGNAL ;
    ANTENNADIFFAREA 0.445500 ;
    PORT
      LAYER met3 ;
        RECT 0.000 125.840 4.000 126.440 ;
    END
  END slave_2_dat_o[1]
  PIN slave_2_dat_o[20]
    DIRECTION OUTPUT ;
    USE SIGNAL ;
    ANTENNADIFFAREA 0.445500 ;
    PORT
      LAYER met3 ;
        RECT 0.000 170.040 4.000 170.640 ;
    END
  END slave_2_dat_o[20]
  PIN slave_2_dat_o[21]
    DIRECTION OUTPUT ;
    USE SIGNAL ;
    ANTENNADIFFAREA 0.445500 ;
    PORT
      LAYER met3 ;
        RECT 387.565 13.640 391.565 14.240 ;
    END
  END slave_2_dat_o[21]
  PIN slave_2_dat_o[22]
    DIRECTION OUTPUT ;
    USE SIGNAL ;
    ANTENNADIFFAREA 0.445500 ;
    PORT
      LAYER met3 ;
        RECT 387.565 357.040 391.565 357.640 ;
    END
  END slave_2_dat_o[22]
  PIN slave_2_dat_o[23]
    DIRECTION OUTPUT ;
    USE SIGNAL ;
    ANTENNADIFFAREA 0.445500 ;
    PORT
      LAYER met2 ;
        RECT 264.130 398.285 264.410 402.285 ;
    END
  END slave_2_dat_o[23]
  PIN slave_2_dat_o[24]
    DIRECTION OUTPUT ;
    USE SIGNAL ;
    ANTENNADIFFAREA 0.445500 ;
    PORT
      LAYER met3 ;
        RECT 387.565 384.240 391.565 384.840 ;
    END
  END slave_2_dat_o[24]
  PIN slave_2_dat_o[25]
    DIRECTION OUTPUT ;
    USE SIGNAL ;
    ANTENNADIFFAREA 0.445500 ;
    PORT
      LAYER met2 ;
        RECT 151.430 398.285 151.710 402.285 ;
    END
  END slave_2_dat_o[25]
  PIN slave_2_dat_o[26]
    DIRECTION OUTPUT ;
    USE SIGNAL ;
    ANTENNADIFFAREA 0.445500 ;
    PORT
      LAYER met3 ;
        RECT 387.565 17.040 391.565 17.640 ;
    END
  END slave_2_dat_o[26]
  PIN slave_2_dat_o[27]
    DIRECTION OUTPUT ;
    USE SIGNAL ;
    ANTENNADIFFAREA 0.445500 ;
    PORT
      LAYER met2 ;
        RECT 64.490 398.285 64.770 402.285 ;
    END
  END slave_2_dat_o[27]
  PIN slave_2_dat_o[28]
    DIRECTION OUTPUT ;
    USE SIGNAL ;
    ANTENNADIFFAREA 0.445500 ;
    PORT
      LAYER met3 ;
        RECT 0.000 380.840 4.000 381.440 ;
    END
  END slave_2_dat_o[28]
  PIN slave_2_dat_o[29]
    DIRECTION OUTPUT ;
    USE SIGNAL ;
    ANTENNADIFFAREA 0.445500 ;
    PORT
      LAYER met3 ;
        RECT 387.565 367.240 391.565 367.840 ;
    END
  END slave_2_dat_o[29]
  PIN slave_2_dat_o[2]
    DIRECTION OUTPUT ;
    USE SIGNAL ;
    ANTENNADIFFAREA 0.445500 ;
    PORT
      LAYER met3 ;
        RECT 0.000 47.640 4.000 48.240 ;
    END
  END slave_2_dat_o[2]
  PIN slave_2_dat_o[30]
    DIRECTION OUTPUT ;
    USE SIGNAL ;
    ANTENNADIFFAREA 0.445500 ;
    PORT
      LAYER met2 ;
        RECT 357.510 398.285 357.790 402.285 ;
    END
  END slave_2_dat_o[30]
  PIN slave_2_dat_o[31]
    DIRECTION OUTPUT ;
    USE SIGNAL ;
    ANTENNADIFFAREA 0.445500 ;
    PORT
      LAYER met2 ;
        RECT 296.330 398.285 296.610 402.285 ;
    END
  END slave_2_dat_o[31]
  PIN slave_2_dat_o[3]
    DIRECTION OUTPUT ;
    USE SIGNAL ;
    ANTENNADIFFAREA 0.445500 ;
    PORT
      LAYER met3 ;
        RECT 0.000 64.640 4.000 65.240 ;
    END
  END slave_2_dat_o[3]
  PIN slave_2_dat_o[4]
    DIRECTION OUTPUT ;
    USE SIGNAL ;
    ANTENNADIFFAREA 0.445500 ;
    PORT
      LAYER met3 ;
        RECT 0.000 40.840 4.000 41.440 ;
    END
  END slave_2_dat_o[4]
  PIN slave_2_dat_o[5]
    DIRECTION OUTPUT ;
    USE SIGNAL ;
    ANTENNADIFFAREA 0.445500 ;
    PORT
      LAYER met3 ;
        RECT 0.000 129.240 4.000 129.840 ;
    END
  END slave_2_dat_o[5]
  PIN slave_2_dat_o[6]
    DIRECTION OUTPUT ;
    USE SIGNAL ;
    ANTENNADIFFAREA 0.445500 ;
    PORT
      LAYER met3 ;
        RECT 0.000 108.840 4.000 109.440 ;
    END
  END slave_2_dat_o[6]
  PIN slave_2_dat_o[7]
    DIRECTION OUTPUT ;
    USE SIGNAL ;
    ANTENNADIFFAREA 0.445500 ;
    PORT
      LAYER met3 ;
        RECT 0.000 115.640 4.000 116.240 ;
    END
  END slave_2_dat_o[7]
  PIN slave_2_dat_o[8]
    DIRECTION OUTPUT ;
    USE SIGNAL ;
    ANTENNADIFFAREA 0.445500 ;
    PORT
      LAYER met3 ;
        RECT 0.000 200.640 4.000 201.240 ;
    END
  END slave_2_dat_o[8]
  PIN slave_2_dat_o[9]
    DIRECTION OUTPUT ;
    USE SIGNAL ;
    ANTENNADIFFAREA 0.445500 ;
    PORT
      LAYER met3 ;
        RECT 0.000 302.640 4.000 303.240 ;
    END
  END slave_2_dat_o[9]
  PIN slave_3_dat_i[0]
    DIRECTION INPUT ;
    USE SIGNAL ;
    ANTENNAGATEAREA 0.631200 ;
    ANTENNADIFFAREA 0.434700 ;
    PORT
      LAYER met3 ;
        RECT 0.000 81.640 4.000 82.240 ;
    END
  END slave_3_dat_i[0]
  PIN slave_3_dat_i[10]
    DIRECTION INPUT ;
    USE SIGNAL ;
    PORT
      LAYER met3 ;
        RECT 387.565 312.840 391.565 313.440 ;
    END
  END slave_3_dat_i[10]
  PIN slave_3_dat_i[11]
    DIRECTION INPUT ;
    USE SIGNAL ;
    PORT
      LAYER met3 ;
        RECT 387.565 278.840 391.565 279.440 ;
    END
  END slave_3_dat_i[11]
  PIN slave_3_dat_i[12]
    DIRECTION INPUT ;
    USE SIGNAL ;
    PORT
      LAYER met3 ;
        RECT 387.565 309.440 391.565 310.040 ;
    END
  END slave_3_dat_i[12]
  PIN slave_3_dat_i[13]
    DIRECTION INPUT ;
    USE SIGNAL ;
    PORT
      LAYER met3 ;
        RECT 387.565 238.040 391.565 238.640 ;
    END
  END slave_3_dat_i[13]
  PIN slave_3_dat_i[14]
    DIRECTION INPUT ;
    USE SIGNAL ;
    PORT
      LAYER met3 ;
        RECT 387.565 132.640 391.565 133.240 ;
    END
  END slave_3_dat_i[14]
  PIN slave_3_dat_i[15]
    DIRECTION INPUT ;
    USE SIGNAL ;
    PORT
      LAYER met3 ;
        RECT 387.565 289.040 391.565 289.640 ;
    END
  END slave_3_dat_i[15]
  PIN slave_3_dat_i[16]
    DIRECTION INPUT ;
    USE SIGNAL ;
    PORT
      LAYER met3 ;
        RECT 387.565 340.040 391.565 340.640 ;
    END
  END slave_3_dat_i[16]
  PIN slave_3_dat_i[17]
    DIRECTION INPUT ;
    USE SIGNAL ;
    PORT
      LAYER met3 ;
        RECT 387.565 78.240 391.565 78.840 ;
    END
  END slave_3_dat_i[17]
  PIN slave_3_dat_i[18]
    DIRECTION INPUT ;
    USE SIGNAL ;
    PORT
      LAYER met3 ;
        RECT 387.565 71.440 391.565 72.040 ;
    END
  END slave_3_dat_i[18]
  PIN slave_3_dat_i[19]
    DIRECTION INPUT ;
    USE SIGNAL ;
    PORT
      LAYER met3 ;
        RECT 387.565 125.840 391.565 126.440 ;
    END
  END slave_3_dat_i[19]
  PIN slave_3_dat_i[1]
    DIRECTION INPUT ;
    USE SIGNAL ;
    PORT
      LAYER met3 ;
        RECT 387.565 261.840 391.565 262.440 ;
    END
  END slave_3_dat_i[1]
  PIN slave_3_dat_i[20]
    DIRECTION INPUT ;
    USE SIGNAL ;
    PORT
      LAYER met3 ;
        RECT 387.565 122.440 391.565 123.040 ;
    END
  END slave_3_dat_i[20]
  PIN slave_3_dat_i[21]
    DIRECTION INPUT ;
    USE SIGNAL ;
    PORT
      LAYER met3 ;
        RECT 387.565 54.440 391.565 55.040 ;
    END
  END slave_3_dat_i[21]
  PIN slave_3_dat_i[22]
    DIRECTION INPUT ;
    USE SIGNAL ;
    PORT
      LAYER met3 ;
        RECT 387.565 326.440 391.565 327.040 ;
    END
  END slave_3_dat_i[22]
  PIN slave_3_dat_i[23]
    DIRECTION INPUT ;
    USE SIGNAL ;
    PORT
      LAYER met3 ;
        RECT 387.565 88.440 391.565 89.040 ;
    END
  END slave_3_dat_i[23]
  PIN slave_3_dat_i[24]
    DIRECTION INPUT ;
    USE SIGNAL ;
    PORT
      LAYER met3 ;
        RECT 387.565 227.840 391.565 228.440 ;
    END
  END slave_3_dat_i[24]
  PIN slave_3_dat_i[25]
    DIRECTION INPUT ;
    USE SIGNAL ;
    PORT
      LAYER met3 ;
        RECT 387.565 251.640 391.565 252.240 ;
    END
  END slave_3_dat_i[25]
  PIN slave_3_dat_i[26]
    DIRECTION INPUT ;
    USE SIGNAL ;
    PORT
      LAYER met3 ;
        RECT 387.565 61.240 391.565 61.840 ;
    END
  END slave_3_dat_i[26]
  PIN slave_3_dat_i[27]
    DIRECTION INPUT ;
    USE SIGNAL ;
    PORT
      LAYER met3 ;
        RECT 387.565 292.440 391.565 293.040 ;
    END
  END slave_3_dat_i[27]
  PIN slave_3_dat_i[28]
    DIRECTION INPUT ;
    USE SIGNAL ;
    PORT
      LAYER met3 ;
        RECT 387.565 115.640 391.565 116.240 ;
    END
  END slave_3_dat_i[28]
  PIN slave_3_dat_i[29]
    DIRECTION INPUT ;
    USE SIGNAL ;
    PORT
      LAYER met3 ;
        RECT 387.565 156.440 391.565 157.040 ;
    END
  END slave_3_dat_i[29]
  PIN slave_3_dat_i[2]
    DIRECTION INPUT ;
    USE SIGNAL ;
    PORT
      LAYER met3 ;
        RECT 387.565 285.640 391.565 286.240 ;
    END
  END slave_3_dat_i[2]
  PIN slave_3_dat_i[30]
    DIRECTION INPUT ;
    USE SIGNAL ;
    PORT
      LAYER met3 ;
        RECT 387.565 329.840 391.565 330.440 ;
    END
  END slave_3_dat_i[30]
  PIN slave_3_dat_i[31]
    DIRECTION INPUT ;
    USE SIGNAL ;
    PORT
      LAYER met3 ;
        RECT 387.565 221.040 391.565 221.640 ;
    END
  END slave_3_dat_i[31]
  PIN slave_3_dat_i[3]
    DIRECTION INPUT ;
    USE SIGNAL ;
    PORT
      LAYER met3 ;
        RECT 387.565 149.640 391.565 150.240 ;
    END
  END slave_3_dat_i[3]
  PIN slave_3_dat_i[4]
    DIRECTION INPUT ;
    USE SIGNAL ;
    PORT
      LAYER met3 ;
        RECT 387.565 85.040 391.565 85.640 ;
    END
  END slave_3_dat_i[4]
  PIN slave_3_dat_i[5]
    DIRECTION INPUT ;
    USE SIGNAL ;
    PORT
      LAYER met3 ;
        RECT 387.565 323.040 391.565 323.640 ;
    END
  END slave_3_dat_i[5]
  PIN slave_3_dat_i[6]
    DIRECTION INPUT ;
    USE SIGNAL ;
    PORT
      LAYER met3 ;
        RECT 387.565 316.240 391.565 316.840 ;
    END
  END slave_3_dat_i[6]
  PIN slave_3_dat_i[7]
    DIRECTION INPUT ;
    USE SIGNAL ;
    PORT
      LAYER met3 ;
        RECT 387.565 394.440 391.565 395.040 ;
    END
  END slave_3_dat_i[7]
  PIN slave_3_dat_i[8]
    DIRECTION INPUT ;
    USE SIGNAL ;
    PORT
      LAYER met3 ;
        RECT 387.565 306.040 391.565 306.640 ;
    END
  END slave_3_dat_i[8]
  PIN slave_3_dat_i[9]
    DIRECTION INPUT ;
    USE SIGNAL ;
    PORT
      LAYER met3 ;
        RECT 387.565 224.440 391.565 225.040 ;
    END
  END slave_3_dat_i[9]
  PIN slave_3_dat_o[0]
    DIRECTION OUTPUT ;
    USE SIGNAL ;
    ANTENNADIFFAREA 0.445500 ;
    PORT
      LAYER met3 ;
        RECT 0.000 27.240 4.000 27.840 ;
    END
  END slave_3_dat_o[0]
  PIN slave_3_dat_o[10]
    DIRECTION OUTPUT ;
    USE SIGNAL ;
    ANTENNADIFFAREA 0.445500 ;
    PORT
      LAYER met3 ;
        RECT 0.000 224.440 4.000 225.040 ;
    END
  END slave_3_dat_o[10]
  PIN slave_3_dat_o[11]
    DIRECTION OUTPUT ;
    USE SIGNAL ;
    ANTENNADIFFAREA 0.445500 ;
    PORT
      LAYER met3 ;
        RECT 0.000 309.440 4.000 310.040 ;
    END
  END slave_3_dat_o[11]
  PIN slave_3_dat_o[12]
    DIRECTION OUTPUT ;
    USE SIGNAL ;
    ANTENNADIFFAREA 0.445500 ;
    PORT
      LAYER met3 ;
        RECT 0.000 268.640 4.000 269.240 ;
    END
  END slave_3_dat_o[12]
  PIN slave_3_dat_o[13]
    DIRECTION OUTPUT ;
    USE SIGNAL ;
    ANTENNADIFFAREA 0.445500 ;
    PORT
      LAYER met3 ;
        RECT 0.000 272.040 4.000 272.640 ;
    END
  END slave_3_dat_o[13]
  PIN slave_3_dat_o[14]
    DIRECTION OUTPUT ;
    USE SIGNAL ;
    ANTENNADIFFAREA 0.445500 ;
    PORT
      LAYER met3 ;
        RECT 0.000 275.440 4.000 276.040 ;
    END
  END slave_3_dat_o[14]
  PIN slave_3_dat_o[15]
    DIRECTION OUTPUT ;
    USE SIGNAL ;
    ANTENNADIFFAREA 0.445500 ;
    PORT
      LAYER met3 ;
        RECT 0.000 278.840 4.000 279.440 ;
    END
  END slave_3_dat_o[15]
  PIN slave_3_dat_o[16]
    DIRECTION OUTPUT ;
    USE SIGNAL ;
    ANTENNADIFFAREA 0.445500 ;
    PORT
      LAYER met3 ;
        RECT 387.565 23.840 391.565 24.440 ;
    END
  END slave_3_dat_o[16]
  PIN slave_3_dat_o[17]
    DIRECTION OUTPUT ;
    USE SIGNAL ;
    ANTENNADIFFAREA 0.445500 ;
    PORT
      LAYER met3 ;
        RECT 387.565 176.840 391.565 177.440 ;
    END
  END slave_3_dat_o[17]
  PIN slave_3_dat_o[18]
    DIRECTION OUTPUT ;
    USE SIGNAL ;
    ANTENNADIFFAREA 0.445500 ;
    PORT
      LAYER met3 ;
        RECT 387.565 10.240 391.565 10.840 ;
    END
  END slave_3_dat_o[18]
  PIN slave_3_dat_o[19]
    DIRECTION OUTPUT ;
    USE SIGNAL ;
    ANTENNADIFFAREA 0.445500 ;
    PORT
      LAYER met3 ;
        RECT 387.565 40.840 391.565 41.440 ;
    END
  END slave_3_dat_o[19]
  PIN slave_3_dat_o[1]
    DIRECTION OUTPUT ;
    USE SIGNAL ;
    ANTENNADIFFAREA 0.445500 ;
    PORT
      LAYER met3 ;
        RECT 0.000 85.040 4.000 85.640 ;
    END
  END slave_3_dat_o[1]
  PIN slave_3_dat_o[20]
    DIRECTION OUTPUT ;
    USE SIGNAL ;
    ANTENNADIFFAREA 0.445500 ;
    PORT
      LAYER met3 ;
        RECT 0.000 159.840 4.000 160.440 ;
    END
  END slave_3_dat_o[20]
  PIN slave_3_dat_o[21]
    DIRECTION OUTPUT ;
    USE SIGNAL ;
    ANTENNADIFFAREA 0.445500 ;
    PORT
      LAYER met3 ;
        RECT 387.565 0.040 391.565 0.640 ;
    END
  END slave_3_dat_o[21]
  PIN slave_3_dat_o[22]
    DIRECTION OUTPUT ;
    USE SIGNAL ;
    ANTENNADIFFAREA 0.445500 ;
    PORT
      LAYER met3 ;
        RECT 387.565 350.240 391.565 350.840 ;
    END
  END slave_3_dat_o[22]
  PIN slave_3_dat_o[23]
    DIRECTION OUTPUT ;
    USE SIGNAL ;
    ANTENNADIFFAREA 0.445500 ;
    PORT
      LAYER met2 ;
        RECT 260.910 398.285 261.190 402.285 ;
    END
  END slave_3_dat_o[23]
  PIN slave_3_dat_o[24]
    DIRECTION OUTPUT ;
    USE SIGNAL ;
    ANTENNADIFFAREA 0.445500 ;
    PORT
      LAYER met3 ;
        RECT 387.565 387.640 391.565 388.240 ;
    END
  END slave_3_dat_o[24]
  PIN slave_3_dat_o[25]
    DIRECTION OUTPUT ;
    USE SIGNAL ;
    ANTENNADIFFAREA 0.445500 ;
    PORT
      LAYER met2 ;
        RECT 144.990 398.285 145.270 402.285 ;
    END
  END slave_3_dat_o[25]
  PIN slave_3_dat_o[26]
    DIRECTION OUTPUT ;
    USE SIGNAL ;
    ANTENNADIFFAREA 0.445500 ;
    PORT
      LAYER met3 ;
        RECT 387.565 37.440 391.565 38.040 ;
    END
  END slave_3_dat_o[26]
  PIN slave_3_dat_o[27]
    DIRECTION OUTPUT ;
    USE SIGNAL ;
    ANTENNADIFFAREA 0.445500 ;
    PORT
      LAYER met2 ;
        RECT 58.050 398.285 58.330 402.285 ;
    END
  END slave_3_dat_o[27]
  PIN slave_3_dat_o[28]
    DIRECTION OUTPUT ;
    USE SIGNAL ;
    ANTENNADIFFAREA 0.445500 ;
    PORT
      LAYER met3 ;
        RECT 0.000 374.040 4.000 374.640 ;
    END
  END slave_3_dat_o[28]
  PIN slave_3_dat_o[29]
    DIRECTION OUTPUT ;
    USE SIGNAL ;
    ANTENNADIFFAREA 0.445500 ;
    PORT
      LAYER met3 ;
        RECT 387.565 370.640 391.565 371.240 ;
    END
  END slave_3_dat_o[29]
  PIN slave_3_dat_o[2]
    DIRECTION OUTPUT ;
    USE SIGNAL ;
    ANTENNADIFFAREA 0.445500 ;
    PORT
      LAYER met3 ;
        RECT 0.000 119.040 4.000 119.640 ;
    END
  END slave_3_dat_o[2]
  PIN slave_3_dat_o[30]
    DIRECTION OUTPUT ;
    USE SIGNAL ;
    ANTENNADIFFAREA 0.445500 ;
    PORT
      LAYER met2 ;
        RECT 360.730 398.285 361.010 402.285 ;
    END
  END slave_3_dat_o[30]
  PIN slave_3_dat_o[31]
    DIRECTION OUTPUT ;
    USE SIGNAL ;
    ANTENNADIFFAREA 0.445500 ;
    PORT
      LAYER met2 ;
        RECT 299.550 398.285 299.830 402.285 ;
    END
  END slave_3_dat_o[31]
  PIN slave_3_dat_o[3]
    DIRECTION OUTPUT ;
    USE SIGNAL ;
    ANTENNADIFFAREA 0.445500 ;
    PORT
      LAYER met3 ;
        RECT 0.000 102.040 4.000 102.640 ;
    END
  END slave_3_dat_o[3]
  PIN slave_3_dat_o[4]
    DIRECTION OUTPUT ;
    USE SIGNAL ;
    ANTENNADIFFAREA 0.445500 ;
    PORT
      LAYER met3 ;
        RECT 0.000 37.440 4.000 38.040 ;
    END
  END slave_3_dat_o[4]
  PIN slave_3_dat_o[5]
    DIRECTION OUTPUT ;
    USE SIGNAL ;
    ANTENNADIFFAREA 0.445500 ;
    PORT
      LAYER met3 ;
        RECT 0.000 61.240 4.000 61.840 ;
    END
  END slave_3_dat_o[5]
  PIN slave_3_dat_o[6]
    DIRECTION OUTPUT ;
    USE SIGNAL ;
    ANTENNADIFFAREA 0.445500 ;
    PORT
      LAYER met3 ;
        RECT 0.000 34.040 4.000 34.640 ;
    END
  END slave_3_dat_o[6]
  PIN slave_3_dat_o[7]
    DIRECTION OUTPUT ;
    USE SIGNAL ;
    ANTENNADIFFAREA 0.445500 ;
    PORT
      LAYER met3 ;
        RECT 0.000 122.440 4.000 123.040 ;
    END
  END slave_3_dat_o[7]
  PIN slave_3_dat_o[8]
    DIRECTION OUTPUT ;
    USE SIGNAL ;
    ANTENNADIFFAREA 0.445500 ;
    PORT
      LAYER met3 ;
        RECT 0.000 193.840 4.000 194.440 ;
    END
  END slave_3_dat_o[8]
  PIN slave_3_dat_o[9]
    DIRECTION OUTPUT ;
    USE SIGNAL ;
    ANTENNADIFFAREA 0.445500 ;
    PORT
      LAYER met3 ;
        RECT 0.000 306.040 4.000 306.640 ;
    END
  END slave_3_dat_o[9]
  PIN slave_ack_i[0]
    DIRECTION INPUT ;
    USE SIGNAL ;
    ANTENNAGATEAREA 0.631200 ;
    ANTENNADIFFAREA 0.434700 ;
    PORT
      LAYER met3 ;
        RECT 0.000 57.840 4.000 58.440 ;
    END
  END slave_ack_i[0]
  PIN slave_ack_i[1]
    DIRECTION INPUT ;
    USE SIGNAL ;
    ANTENNAGATEAREA 0.631200 ;
    ANTENNADIFFAREA 0.434700 ;
    PORT
      LAYER met3 ;
        RECT 0.000 30.640 4.000 31.240 ;
    END
  END slave_ack_i[1]
  PIN slave_ack_i[2]
    DIRECTION INPUT ;
    USE SIGNAL ;
    ANTENNAGATEAREA 0.631200 ;
    ANTENNADIFFAREA 0.434700 ;
    PORT
      LAYER met3 ;
        RECT 0.000 78.240 4.000 78.840 ;
    END
  END slave_ack_i[2]
  PIN slave_ack_i[3]
    DIRECTION INPUT ;
    USE SIGNAL ;
    ANTENNAGATEAREA 0.631200 ;
    ANTENNADIFFAREA 0.434700 ;
    PORT
      LAYER met3 ;
        RECT 0.000 88.440 4.000 89.040 ;
    END
  END slave_ack_i[3]
  PIN slave_cyc_o
    DIRECTION OUTPUT ;
    USE SIGNAL ;
    ANTENNADIFFAREA 0.445500 ;
    PORT
      LAYER met3 ;
        RECT 387.565 91.840 391.565 92.440 ;
    END
  END slave_cyc_o
  PIN slave_stb_o
    DIRECTION OUTPUT ;
    USE SIGNAL ;
    ANTENNADIFFAREA 0.445500 ;
    PORT
      LAYER met3 ;
        RECT 387.565 98.640 391.565 99.240 ;
    END
  END slave_stb_o
  PIN slave_we_o
    DIRECTION OUTPUT ;
    USE SIGNAL ;
    ANTENNADIFFAREA 0.445500 ;
    PORT
      LAYER met3 ;
        RECT 387.565 102.040 391.565 102.640 ;
    END
  END slave_we_o
  PIN wb_clk_i
    DIRECTION INPUT ;
    USE SIGNAL ;
    ANTENNAGATEAREA 1.286700 ;
    ANTENNADIFFAREA 0.434700 ;
    PORT
      LAYER met3 ;
        RECT 0.000 323.040 4.000 323.640 ;
    END
  END wb_clk_i
  PIN wb_rst_i
    DIRECTION INPUT ;
    USE SIGNAL ;
    ANTENNAGATEAREA 0.631200 ;
    ANTENNADIFFAREA 0.434700 ;
    PORT
      LAYER met3 ;
        RECT 0.000 319.640 4.000 320.240 ;
    END
  END wb_rst_i
  PIN wbs_ack_o
    DIRECTION OUTPUT ;
    USE SIGNAL ;
    ANTENNADIFFAREA 0.445500 ;
    PORT
      LAYER met3 ;
        RECT 387.565 95.240 391.565 95.840 ;
    END
  END wbs_ack_o
  PIN wbs_adr_i[0]
    DIRECTION INPUT ;
    USE SIGNAL ;
    ANTENNAGATEAREA 0.631200 ;
    ANTENNADIFFAREA 0.434700 ;
    PORT
      LAYER met3 ;
        RECT 387.565 214.240 391.565 214.840 ;
    END
  END wbs_adr_i[0]
  PIN wbs_adr_i[10]
    DIRECTION INPUT ;
    USE SIGNAL ;
    PORT
      LAYER met3 ;
        RECT 387.565 136.040 391.565 136.640 ;
    END
  END wbs_adr_i[10]
  PIN wbs_adr_i[11]
    DIRECTION INPUT ;
    USE SIGNAL ;
    PORT
      LAYER met3 ;
        RECT 387.565 319.640 391.565 320.240 ;
    END
  END wbs_adr_i[11]
  PIN wbs_adr_i[12]
    DIRECTION INPUT ;
    USE SIGNAL ;
    ANTENNAGATEAREA 0.631200 ;
    ANTENNADIFFAREA 0.434700 ;
    PORT
      LAYER met3 ;
        RECT 0.000 71.440 4.000 72.040 ;
    END
  END wbs_adr_i[12]
  PIN wbs_adr_i[13]
    DIRECTION INPUT ;
    USE SIGNAL ;
    ANTENNAGATEAREA 0.631200 ;
    ANTENNADIFFAREA 0.434700 ;
    PORT
      LAYER met3 ;
        RECT 0.000 54.440 4.000 55.040 ;
    END
  END wbs_adr_i[13]
  PIN wbs_adr_i[14]
    DIRECTION INPUT ;
    USE SIGNAL ;
    ANTENNAGATEAREA 0.631200 ;
    ANTENNADIFFAREA 0.434700 ;
    PORT
      LAYER met3 ;
        RECT 0.000 44.240 4.000 44.840 ;
    END
  END wbs_adr_i[14]
  PIN wbs_adr_i[15]
    DIRECTION INPUT ;
    USE SIGNAL ;
    ANTENNAGATEAREA 0.631200 ;
    ANTENNADIFFAREA 0.434700 ;
    PORT
      LAYER met3 ;
        RECT 0.000 95.240 4.000 95.840 ;
    END
  END wbs_adr_i[15]
  PIN wbs_adr_i[16]
    DIRECTION INPUT ;
    USE SIGNAL ;
    PORT
      LAYER met3 ;
        RECT 387.565 401.240 391.565 401.840 ;
    END
  END wbs_adr_i[16]
  PIN wbs_adr_i[17]
    DIRECTION INPUT ;
    USE SIGNAL ;
    PORT
      LAYER met3 ;
        RECT 387.565 197.240 391.565 197.840 ;
    END
  END wbs_adr_i[17]
  PIN wbs_adr_i[18]
    DIRECTION INPUT ;
    USE SIGNAL ;
    PORT
      LAYER met3 ;
        RECT 387.565 234.640 391.565 235.240 ;
    END
  END wbs_adr_i[18]
  PIN wbs_adr_i[19]
    DIRECTION INPUT ;
    USE SIGNAL ;
    PORT
      LAYER met3 ;
        RECT 387.565 146.240 391.565 146.840 ;
    END
  END wbs_adr_i[19]
  PIN wbs_adr_i[1]
    DIRECTION INPUT ;
    USE SIGNAL ;
    ANTENNAGATEAREA 0.631200 ;
    ANTENNADIFFAREA 0.434700 ;
    PORT
      LAYER met3 ;
        RECT 387.565 210.840 391.565 211.440 ;
    END
  END wbs_adr_i[1]
  PIN wbs_adr_i[20]
    DIRECTION INPUT ;
    USE SIGNAL ;
    PORT
      LAYER met3 ;
        RECT 387.565 81.640 391.565 82.240 ;
    END
  END wbs_adr_i[20]
  PIN wbs_adr_i[21]
    DIRECTION INPUT ;
    USE SIGNAL ;
    PORT
      LAYER met3 ;
        RECT 387.565 333.240 391.565 333.840 ;
    END
  END wbs_adr_i[21]
  PIN wbs_adr_i[22]
    DIRECTION INPUT ;
    USE SIGNAL ;
    PORT
      LAYER met3 ;
        RECT 387.565 74.840 391.565 75.440 ;
    END
  END wbs_adr_i[22]
  PIN wbs_adr_i[23]
    DIRECTION INPUT ;
    USE SIGNAL ;
    PORT
      LAYER met3 ;
        RECT 387.565 68.040 391.565 68.640 ;
    END
  END wbs_adr_i[23]
  PIN wbs_adr_i[24]
    DIRECTION INPUT ;
    USE SIGNAL ;
    PORT
      LAYER met3 ;
        RECT 387.565 57.840 391.565 58.440 ;
    END
  END wbs_adr_i[24]
  PIN wbs_adr_i[25]
    DIRECTION INPUT ;
    USE SIGNAL ;
    PORT
      LAYER met3 ;
        RECT 387.565 268.640 391.565 269.240 ;
    END
  END wbs_adr_i[25]
  PIN wbs_adr_i[26]
    DIRECTION INPUT ;
    USE SIGNAL ;
    PORT
      LAYER met3 ;
        RECT 387.565 153.040 391.565 153.640 ;
    END
  END wbs_adr_i[26]
  PIN wbs_adr_i[27]
    DIRECTION INPUT ;
    USE SIGNAL ;
    PORT
      LAYER met3 ;
        RECT 387.565 302.640 391.565 303.240 ;
    END
  END wbs_adr_i[27]
  PIN wbs_adr_i[28]
    DIRECTION INPUT ;
    USE SIGNAL ;
    PORT
      LAYER met3 ;
        RECT 387.565 241.440 391.565 242.040 ;
    END
  END wbs_adr_i[28]
  PIN wbs_adr_i[29]
    DIRECTION INPUT ;
    USE SIGNAL ;
    PORT
      LAYER met3 ;
        RECT 387.565 159.840 391.565 160.440 ;
    END
  END wbs_adr_i[29]
  PIN wbs_adr_i[2]
    DIRECTION INPUT ;
    USE SIGNAL ;
    ANTENNAGATEAREA 0.631200 ;
    ANTENNADIFFAREA 0.434700 ;
    PORT
      LAYER met3 ;
        RECT 387.565 204.040 391.565 204.640 ;
    END
  END wbs_adr_i[2]
  PIN wbs_adr_i[30]
    DIRECTION INPUT ;
    USE SIGNAL ;
    PORT
      LAYER met3 ;
        RECT 387.565 112.240 391.565 112.840 ;
    END
  END wbs_adr_i[30]
  PIN wbs_adr_i[31]
    DIRECTION INPUT ;
    USE SIGNAL ;
    PORT
      LAYER met3 ;
        RECT 387.565 265.240 391.565 265.840 ;
    END
  END wbs_adr_i[31]
  PIN wbs_adr_i[3]
    DIRECTION INPUT ;
    USE SIGNAL ;
    ANTENNAGATEAREA 0.631200 ;
    ANTENNADIFFAREA 0.434700 ;
    PORT
      LAYER met3 ;
        RECT 387.565 207.440 391.565 208.040 ;
    END
  END wbs_adr_i[3]
  PIN wbs_adr_i[4]
    DIRECTION INPUT ;
    USE SIGNAL ;
    PORT
      LAYER met3 ;
        RECT 387.565 336.640 391.565 337.240 ;
    END
  END wbs_adr_i[4]
  PIN wbs_adr_i[5]
    DIRECTION INPUT ;
    USE SIGNAL ;
    PORT
      LAYER met3 ;
        RECT 387.565 193.840 391.565 194.440 ;
    END
  END wbs_adr_i[5]
  PIN wbs_adr_i[6]
    DIRECTION INPUT ;
    USE SIGNAL ;
    PORT
      LAYER met3 ;
        RECT 387.565 129.240 391.565 129.840 ;
    END
  END wbs_adr_i[6]
  PIN wbs_adr_i[7]
    DIRECTION INPUT ;
    USE SIGNAL ;
    PORT
      LAYER met3 ;
        RECT 387.565 244.840 391.565 245.440 ;
    END
  END wbs_adr_i[7]
  PIN wbs_adr_i[8]
    DIRECTION INPUT ;
    USE SIGNAL ;
    PORT
      LAYER met3 ;
        RECT 387.565 397.840 391.565 398.440 ;
    END
  END wbs_adr_i[8]
  PIN wbs_adr_i[9]
    DIRECTION INPUT ;
    USE SIGNAL ;
    PORT
      LAYER met3 ;
        RECT 387.565 248.240 391.565 248.840 ;
    END
  END wbs_adr_i[9]
  PIN wbs_cyc_i
    DIRECTION INPUT ;
    USE SIGNAL ;
    ANTENNAGATEAREA 0.647700 ;
    ANTENNADIFFAREA 0.434700 ;
    PORT
      LAYER met3 ;
        RECT 387.565 108.840 391.565 109.440 ;
    END
  END wbs_cyc_i
  PIN wbs_dat_i[0]
    DIRECTION INPUT ;
    USE SIGNAL ;
    ANTENNAGATEAREA 0.647700 ;
    ANTENNADIFFAREA 0.434700 ;
    PORT
      LAYER met3 ;
        RECT 0.000 74.840 4.000 75.440 ;
    END
  END wbs_dat_i[0]
  PIN wbs_dat_i[10]
    DIRECTION INPUT ;
    USE SIGNAL ;
    ANTENNAGATEAREA 0.647700 ;
    ANTENNADIFFAREA 0.434700 ;
    PORT
      LAYER met3 ;
        RECT 0.000 227.840 4.000 228.440 ;
    END
  END wbs_dat_i[10]
  PIN wbs_dat_i[11]
    DIRECTION INPUT ;
    USE SIGNAL ;
    ANTENNAGATEAREA 0.593700 ;
    ANTENNADIFFAREA 0.434700 ;
    PORT
      LAYER met3 ;
        RECT 0.000 210.840 4.000 211.440 ;
    END
  END wbs_dat_i[11]
  PIN wbs_dat_i[12]
    DIRECTION INPUT ;
    USE SIGNAL ;
    ANTENNAGATEAREA 0.647700 ;
    ANTENNADIFFAREA 0.434700 ;
    PORT
      LAYER met3 ;
        RECT 0.000 292.440 4.000 293.040 ;
    END
  END wbs_dat_i[12]
  PIN wbs_dat_i[13]
    DIRECTION INPUT ;
    USE SIGNAL ;
    ANTENNAGATEAREA 0.593700 ;
    ANTENNADIFFAREA 0.434700 ;
    PORT
      LAYER met3 ;
        RECT 0.000 289.040 4.000 289.640 ;
    END
  END wbs_dat_i[13]
  PIN wbs_dat_i[14]
    DIRECTION INPUT ;
    USE SIGNAL ;
    ANTENNAGATEAREA 0.593700 ;
    ANTENNADIFFAREA 0.434700 ;
    PORT
      LAYER met3 ;
        RECT 0.000 282.240 4.000 282.840 ;
    END
  END wbs_dat_i[14]
  PIN wbs_dat_i[15]
    DIRECTION INPUT ;
    USE SIGNAL ;
    ANTENNAGATEAREA 0.593700 ;
    ANTENNADIFFAREA 0.434700 ;
    PORT
      LAYER met3 ;
        RECT 0.000 285.640 4.000 286.240 ;
    END
  END wbs_dat_i[15]
  PIN wbs_dat_i[16]
    DIRECTION INPUT ;
    USE SIGNAL ;
    ANTENNAGATEAREA 2.524800 ;
    ANTENNADIFFAREA 1.738800 ;
    PORT
      LAYER met3 ;
        RECT 387.565 44.240 391.565 44.840 ;
    END
  END wbs_dat_i[16]
  PIN wbs_dat_i[17]
    DIRECTION INPUT ;
    USE SIGNAL ;
    ANTENNAGATEAREA 2.524800 ;
    ANTENNADIFFAREA 1.738800 ;
    PORT
      LAYER met3 ;
        RECT 387.565 173.440 391.565 174.040 ;
    END
  END wbs_dat_i[17]
  PIN wbs_dat_i[18]
    DIRECTION INPUT ;
    USE SIGNAL ;
    ANTENNAGATEAREA 2.524800 ;
    ANTENNADIFFAREA 1.738800 ;
    PORT
      LAYER met3 ;
        RECT 387.565 3.440 391.565 4.040 ;
    END
  END wbs_dat_i[18]
  PIN wbs_dat_i[19]
    DIRECTION INPUT ;
    USE SIGNAL ;
    ANTENNAGATEAREA 2.524800 ;
    ANTENNADIFFAREA 1.738800 ;
    PORT
      LAYER met3 ;
        RECT 387.565 30.640 391.565 31.240 ;
    END
  END wbs_dat_i[19]
  PIN wbs_dat_i[1]
    DIRECTION INPUT ;
    USE SIGNAL ;
    ANTENNAGATEAREA 0.593700 ;
    ANTENNADIFFAREA 0.434700 ;
    PORT
      LAYER met3 ;
        RECT 0.000 136.040 4.000 136.640 ;
    END
  END wbs_dat_i[1]
  PIN wbs_dat_i[20]
    DIRECTION INPUT ;
    USE SIGNAL ;
    ANTENNAGATEAREA 0.631200 ;
    ANTENNADIFFAREA 0.434700 ;
    PORT
      LAYER met3 ;
        RECT 0.000 173.440 4.000 174.040 ;
    END
  END wbs_dat_i[20]
  PIN wbs_dat_i[21]
    DIRECTION INPUT ;
    USE SIGNAL ;
    ANTENNAGATEAREA 2.524800 ;
    ANTENNADIFFAREA 1.738800 ;
    PORT
      LAYER met3 ;
        RECT 0.000 20.440 4.000 21.040 ;
    END
  END wbs_dat_i[21]
  PIN wbs_dat_i[22]
    DIRECTION INPUT ;
    USE SIGNAL ;
    ANTENNAGATEAREA 2.524800 ;
    ANTENNADIFFAREA 1.738800 ;
    PORT
      LAYER met3 ;
        RECT 387.565 346.840 391.565 347.440 ;
    END
  END wbs_dat_i[22]
  PIN wbs_dat_i[23]
    DIRECTION INPUT ;
    USE SIGNAL ;
    ANTENNAGATEAREA 2.524800 ;
    ANTENNADIFFAREA 1.738800 ;
    PORT
      LAYER met2 ;
        RECT 257.690 398.285 257.970 402.285 ;
    END
  END wbs_dat_i[23]
  PIN wbs_dat_i[24]
    DIRECTION INPUT ;
    USE SIGNAL ;
    ANTENNAGATEAREA 2.524800 ;
    ANTENNADIFFAREA 1.738800 ;
    PORT
      LAYER met3 ;
        RECT 387.565 377.440 391.565 378.040 ;
    END
  END wbs_dat_i[24]
  PIN wbs_dat_i[25]
    DIRECTION INPUT ;
    USE SIGNAL ;
    ANTENNAGATEAREA 2.524800 ;
    ANTENNADIFFAREA 1.738800 ;
    PORT
      LAYER met2 ;
        RECT 141.770 398.285 142.050 402.285 ;
    END
  END wbs_dat_i[25]
  PIN wbs_dat_i[26]
    DIRECTION INPUT ;
    USE SIGNAL ;
    ANTENNAGATEAREA 2.524800 ;
    ANTENNADIFFAREA 1.738800 ;
    PORT
      LAYER met3 ;
        RECT 387.565 6.840 391.565 7.440 ;
    END
  END wbs_dat_i[26]
  PIN wbs_dat_i[27]
    DIRECTION INPUT ;
    USE SIGNAL ;
    ANTENNAGATEAREA 2.524800 ;
    ANTENNADIFFAREA 1.738800 ;
    PORT
      LAYER met2 ;
        RECT 54.830 398.285 55.110 402.285 ;
    END
  END wbs_dat_i[27]
  PIN wbs_dat_i[28]
    DIRECTION INPUT ;
    USE SIGNAL ;
    ANTENNAGATEAREA 2.524800 ;
    ANTENNADIFFAREA 1.738800 ;
    PORT
      LAYER met3 ;
        RECT 0.000 370.640 4.000 371.240 ;
    END
  END wbs_dat_i[28]
  PIN wbs_dat_i[29]
    DIRECTION INPUT ;
    USE SIGNAL ;
    ANTENNAGATEAREA 2.524800 ;
    ANTENNADIFFAREA 1.738800 ;
    PORT
      LAYER met3 ;
        RECT 387.565 360.440 391.565 361.040 ;
    END
  END wbs_dat_i[29]
  PIN wbs_dat_i[2]
    DIRECTION INPUT ;
    USE SIGNAL ;
    ANTENNAGATEAREA 0.631200 ;
    ANTENNADIFFAREA 0.434700 ;
    PORT
      LAYER met3 ;
        RECT 0.000 139.440 4.000 140.040 ;
    END
  END wbs_dat_i[2]
  PIN wbs_dat_i[30]
    DIRECTION INPUT ;
    USE SIGNAL ;
    ANTENNAGATEAREA 2.524800 ;
    ANTENNADIFFAREA 1.738800 ;
    PORT
      LAYER met2 ;
        RECT 351.070 398.285 351.350 402.285 ;
    END
  END wbs_dat_i[30]
  PIN wbs_dat_i[31]
    DIRECTION INPUT ;
    USE SIGNAL ;
    ANTENNAGATEAREA 2.524800 ;
    ANTENNADIFFAREA 1.738800 ;
    PORT
      LAYER met2 ;
        RECT 289.890 398.285 290.170 402.285 ;
    END
  END wbs_dat_i[31]
  PIN wbs_dat_i[3]
    DIRECTION INPUT ;
    USE SIGNAL ;
    ANTENNAGATEAREA 0.631200 ;
    ANTENNADIFFAREA 0.434700 ;
    PORT
      LAYER met3 ;
        RECT 0.000 132.640 4.000 133.240 ;
    END
  END wbs_dat_i[3]
  PIN wbs_dat_i[4]
    DIRECTION INPUT ;
    USE SIGNAL ;
    ANTENNAGATEAREA 0.593700 ;
    ANTENNADIFFAREA 0.434700 ;
    PORT
      LAYER met3 ;
        RECT 0.000 149.640 4.000 150.240 ;
    END
  END wbs_dat_i[4]
  PIN wbs_dat_i[5]
    DIRECTION INPUT ;
    USE SIGNAL ;
    ANTENNAGATEAREA 0.631200 ;
    ANTENNADIFFAREA 0.434700 ;
    PORT
      LAYER met3 ;
        RECT 0.000 142.840 4.000 143.440 ;
    END
  END wbs_dat_i[5]
  PIN wbs_dat_i[6]
    DIRECTION INPUT ;
    USE SIGNAL ;
    ANTENNAGATEAREA 0.647700 ;
    ANTENNADIFFAREA 0.434700 ;
    PORT
      LAYER met3 ;
        RECT 0.000 180.240 4.000 180.840 ;
    END
  END wbs_dat_i[6]
  PIN wbs_dat_i[7]
    DIRECTION INPUT ;
    USE SIGNAL ;
    ANTENNAGATEAREA 0.631200 ;
    ANTENNADIFFAREA 0.434700 ;
    PORT
      LAYER met3 ;
        RECT 0.000 183.640 4.000 184.240 ;
    END
  END wbs_dat_i[7]
  PIN wbs_dat_i[8]
    DIRECTION INPUT ;
    USE SIGNAL ;
    ANTENNAGATEAREA 0.647700 ;
    ANTENNADIFFAREA 0.434700 ;
    PORT
      LAYER met3 ;
        RECT 0.000 190.440 4.000 191.040 ;
    END
  END wbs_dat_i[8]
  PIN wbs_dat_i[9]
    DIRECTION INPUT ;
    USE SIGNAL ;
    ANTENNAGATEAREA 0.593700 ;
    ANTENNADIFFAREA 0.434700 ;
    PORT
      LAYER met3 ;
        RECT 0.000 204.040 4.000 204.640 ;
    END
  END wbs_dat_i[9]
  PIN wbs_dat_o[0]
    DIRECTION OUTPUT ;
    USE SIGNAL ;
    ANTENNADIFFAREA 0.445500 ;
    PORT
      LAYER met3 ;
        RECT 387.565 275.440 391.565 276.040 ;
    END
  END wbs_dat_o[0]
  PIN wbs_dat_o[10]
    DIRECTION OUTPUT ;
    USE SIGNAL ;
    ANTENNADIFFAREA 0.445500 ;
    PORT
      LAYER met3 ;
        RECT 387.565 105.440 391.565 106.040 ;
    END
  END wbs_dat_o[10]
  PIN wbs_dat_o[11]
    DIRECTION OUTPUT ;
    USE SIGNAL ;
    ANTENNADIFFAREA 0.445500 ;
    PORT
      LAYER met3 ;
        RECT 387.565 217.640 391.565 218.240 ;
    END
  END wbs_dat_o[11]
  PIN wbs_dat_o[12]
    DIRECTION OUTPUT ;
    USE SIGNAL ;
    ANTENNADIFFAREA 0.445500 ;
    PORT
      LAYER met3 ;
        RECT 387.565 272.040 391.565 272.640 ;
    END
  END wbs_dat_o[12]
  PIN wbs_dat_o[13]
    DIRECTION OUTPUT ;
    USE SIGNAL ;
    ANTENNADIFFAREA 0.445500 ;
    PORT
      LAYER met3 ;
        RECT 387.565 187.040 391.565 187.640 ;
    END
  END wbs_dat_o[13]
  PIN wbs_dat_o[14]
    DIRECTION OUTPUT ;
    USE SIGNAL ;
    ANTENNADIFFAREA 0.445500 ;
    PORT
      LAYER met3 ;
        RECT 387.565 139.440 391.565 140.040 ;
    END
  END wbs_dat_o[14]
  PIN wbs_dat_o[15]
    DIRECTION OUTPUT ;
    USE SIGNAL ;
    ANTENNADIFFAREA 0.445500 ;
    PORT
      LAYER met3 ;
        RECT 387.565 255.040 391.565 255.640 ;
    END
  END wbs_dat_o[15]
  PIN wbs_dat_o[16]
    DIRECTION OUTPUT ;
    USE SIGNAL ;
    ANTENNADIFFAREA 0.445500 ;
    PORT
      LAYER met3 ;
        RECT 387.565 282.240 391.565 282.840 ;
    END
  END wbs_dat_o[16]
  PIN wbs_dat_o[17]
    DIRECTION OUTPUT ;
    USE SIGNAL ;
    ANTENNADIFFAREA 0.445500 ;
    PORT
      LAYER met3 ;
        RECT 387.565 200.640 391.565 201.240 ;
    END
  END wbs_dat_o[17]
  PIN wbs_dat_o[18]
    DIRECTION OUTPUT ;
    USE SIGNAL ;
    ANTENNADIFFAREA 0.445500 ;
    PORT
      LAYER met3 ;
        RECT 387.565 142.840 391.565 143.440 ;
    END
  END wbs_dat_o[18]
  PIN wbs_dat_o[19]
    DIRECTION OUTPUT ;
    USE SIGNAL ;
    ANTENNADIFFAREA 0.445500 ;
    PORT
      LAYER met3 ;
        RECT 387.565 231.240 391.565 231.840 ;
    END
  END wbs_dat_o[19]
  PIN wbs_dat_o[1]
    DIRECTION OUTPUT ;
    USE SIGNAL ;
    ANTENNADIFFAREA 0.445500 ;
    PORT
      LAYER met3 ;
        RECT 387.565 163.240 391.565 163.840 ;
    END
  END wbs_dat_o[1]
  PIN wbs_dat_o[20]
    DIRECTION OUTPUT ;
    USE SIGNAL ;
    ANTENNADIFFAREA 0.445500 ;
    PORT
      LAYER met3 ;
        RECT 387.565 295.840 391.565 296.440 ;
    END
  END wbs_dat_o[20]
  PIN wbs_dat_o[21]
    DIRECTION OUTPUT ;
    USE SIGNAL ;
    ANTENNADIFFAREA 0.445500 ;
    PORT
      LAYER met3 ;
        RECT 387.565 190.440 391.565 191.040 ;
    END
  END wbs_dat_o[21]
  PIN wbs_dat_o[22]
    DIRECTION OUTPUT ;
    USE SIGNAL ;
    ANTENNADIFFAREA 0.445500 ;
    PORT
      LAYER met3 ;
        RECT 387.565 119.040 391.565 119.640 ;
    END
  END wbs_dat_o[22]
  PIN wbs_dat_o[23]
    DIRECTION OUTPUT ;
    USE SIGNAL ;
    ANTENNADIFFAREA 0.445500 ;
    PORT
      LAYER met3 ;
        RECT 387.565 258.440 391.565 259.040 ;
    END
  END wbs_dat_o[23]
  PIN wbs_dat_o[24]
    DIRECTION OUTPUT ;
    USE SIGNAL ;
    ANTENNADIFFAREA 0.445500 ;
    PORT
      LAYER met3 ;
        RECT 387.565 299.240 391.565 299.840 ;
    END
  END wbs_dat_o[24]
  PIN wbs_dat_o[25]
    DIRECTION OUTPUT ;
    USE SIGNAL ;
    ANTENNADIFFAREA 0.445500 ;
    PORT
      LAYER met3 ;
        RECT 387.565 170.040 391.565 170.640 ;
    END
  END wbs_dat_o[25]
  PIN wbs_dat_o[26]
    DIRECTION OUTPUT ;
    USE SIGNAL ;
    ANTENNADIFFAREA 0.445500 ;
    PORT
      LAYER met3 ;
        RECT 0.000 112.240 4.000 112.840 ;
    END
  END wbs_dat_o[26]
  PIN wbs_dat_o[27]
    DIRECTION OUTPUT ;
    USE SIGNAL ;
    ANTENNADIFFAREA 0.445500 ;
    PORT
      LAYER met2 ;
        RECT 331.750 398.285 332.030 402.285 ;
    END
  END wbs_dat_o[27]
  PIN wbs_dat_o[28]
    DIRECTION OUTPUT ;
    USE SIGNAL ;
    ANTENNADIFFAREA 0.445500 ;
    PORT
      LAYER met2 ;
        RECT 318.870 398.285 319.150 402.285 ;
    END
  END wbs_dat_o[28]
  PIN wbs_dat_o[29]
    DIRECTION OUTPUT ;
    USE SIGNAL ;
    ANTENNADIFFAREA 0.445500 ;
    PORT
      LAYER met3 ;
        RECT 0.000 163.240 4.000 163.840 ;
    END
  END wbs_dat_o[29]
  PIN wbs_dat_o[2]
    DIRECTION OUTPUT ;
    USE SIGNAL ;
    ANTENNADIFFAREA 0.445500 ;
    PORT
      LAYER met3 ;
        RECT 0.000 98.640 4.000 99.240 ;
    END
  END wbs_dat_o[2]
  PIN wbs_dat_o[30]
    DIRECTION OUTPUT ;
    USE SIGNAL ;
    ANTENNADIFFAREA 0.445500 ;
    PORT
      LAYER met3 ;
        RECT 0.000 146.240 4.000 146.840 ;
    END
  END wbs_dat_o[30]
  PIN wbs_dat_o[31]
    DIRECTION OUTPUT ;
    USE SIGNAL ;
    ANTENNADIFFAREA 0.445500 ;
    PORT
      LAYER met2 ;
        RECT 322.090 398.285 322.370 402.285 ;
    END
  END wbs_dat_o[31]
  PIN wbs_dat_o[3]
    DIRECTION OUTPUT ;
    USE SIGNAL ;
    ANTENNADIFFAREA 0.445500 ;
    PORT
      LAYER met2 ;
        RECT 334.970 398.285 335.250 402.285 ;
    END
  END wbs_dat_o[3]
  PIN wbs_dat_o[4]
    DIRECTION OUTPUT ;
    USE SIGNAL ;
    ANTENNADIFFAREA 0.445500 ;
    PORT
      LAYER met2 ;
        RECT 338.190 398.285 338.470 402.285 ;
    END
  END wbs_dat_o[4]
  PIN wbs_dat_o[5]
    DIRECTION OUTPUT ;
    USE SIGNAL ;
    ANTENNADIFFAREA 0.445500 ;
    PORT
      LAYER met3 ;
        RECT 0.000 187.040 4.000 187.640 ;
    END
  END wbs_dat_o[5]
  PIN wbs_dat_o[6]
    DIRECTION OUTPUT ;
    USE SIGNAL ;
    ANTENNADIFFAREA 0.445500 ;
    PORT
      LAYER met3 ;
        RECT 0.000 105.440 4.000 106.040 ;
    END
  END wbs_dat_o[6]
  PIN wbs_dat_o[7]
    DIRECTION OUTPUT ;
    USE SIGNAL ;
    ANTENNADIFFAREA 0.445500 ;
    PORT
      LAYER met2 ;
        RECT 325.310 398.285 325.590 402.285 ;
    END
  END wbs_dat_o[7]
  PIN wbs_dat_o[8]
    DIRECTION OUTPUT ;
    USE SIGNAL ;
    ANTENNADIFFAREA 0.445500 ;
    PORT
      LAYER met2 ;
        RECT 305.990 398.285 306.270 402.285 ;
    END
  END wbs_dat_o[8]
  PIN wbs_dat_o[9]
    DIRECTION OUTPUT ;
    USE SIGNAL ;
    ANTENNADIFFAREA 0.445500 ;
    PORT
      LAYER met3 ;
        RECT 0.000 166.640 4.000 167.240 ;
    END
  END wbs_dat_o[9]
  PIN wbs_sel_i[0]
    DIRECTION INPUT ;
    USE SIGNAL ;
    ANTENNAGATEAREA 0.647700 ;
    ANTENNADIFFAREA 0.434700 ;
    PORT
      LAYER met3 ;
        RECT 0.000 91.840 4.000 92.440 ;
    END
  END wbs_sel_i[0]
  PIN wbs_sel_i[1]
    DIRECTION INPUT ;
    USE SIGNAL ;
    PORT
      LAYER met2 ;
        RECT 389.710 398.285 389.990 402.285 ;
    END
  END wbs_sel_i[1]
  PIN wbs_sel_i[2]
    DIRECTION INPUT ;
    USE SIGNAL ;
    PORT
      LAYER met2 ;
        RECT 386.490 398.285 386.770 402.285 ;
    END
  END wbs_sel_i[2]
  PIN wbs_sel_i[3]
    DIRECTION INPUT ;
    USE SIGNAL ;
    PORT
      LAYER met2 ;
        RECT 383.270 398.285 383.550 402.285 ;
    END
  END wbs_sel_i[3]
  PIN wbs_stb_i
    DIRECTION INPUT ;
    USE SIGNAL ;
    ANTENNAGATEAREA 0.647700 ;
    ANTENNADIFFAREA 0.434700 ;
    PORT
      LAYER met3 ;
        RECT 0.000 68.040 4.000 68.640 ;
    END
  END wbs_stb_i
  PIN wbs_we_i
    DIRECTION INPUT ;
    USE SIGNAL ;
    ANTENNAGATEAREA 0.647700 ;
    ANTENNADIFFAREA 0.434700 ;
    PORT
      LAYER met3 ;
        RECT 0.000 51.040 4.000 51.640 ;
    END
  END wbs_we_i
  OBS
      LAYER nwell ;
        RECT 5.330 10.760 386.130 389.150 ;
      LAYER li1 ;
        RECT 5.520 10.795 385.940 389.045 ;
      LAYER met1 ;
        RECT 4.210 10.640 385.940 389.200 ;
      LAYER met2 ;
        RECT 4.230 398.005 51.330 398.890 ;
        RECT 52.170 398.005 54.550 398.890 ;
        RECT 55.390 398.005 57.770 398.890 ;
        RECT 58.610 398.005 60.990 398.890 ;
        RECT 61.830 398.005 64.210 398.890 ;
        RECT 65.050 398.005 141.490 398.890 ;
        RECT 142.330 398.005 144.710 398.890 ;
        RECT 145.550 398.005 147.930 398.890 ;
        RECT 148.770 398.005 151.150 398.890 ;
        RECT 151.990 398.005 154.370 398.890 ;
        RECT 155.210 398.005 254.190 398.890 ;
        RECT 255.030 398.005 257.410 398.890 ;
        RECT 258.250 398.005 260.630 398.890 ;
        RECT 261.470 398.005 263.850 398.890 ;
        RECT 264.690 398.005 267.070 398.890 ;
        RECT 267.910 398.005 286.390 398.890 ;
        RECT 287.230 398.005 289.610 398.890 ;
        RECT 290.450 398.005 292.830 398.890 ;
        RECT 293.670 398.005 296.050 398.890 ;
        RECT 296.890 398.005 299.270 398.890 ;
        RECT 300.110 398.005 305.710 398.890 ;
        RECT 306.550 398.005 318.590 398.890 ;
        RECT 319.430 398.005 321.810 398.890 ;
        RECT 322.650 398.005 325.030 398.890 ;
        RECT 325.870 398.005 331.470 398.890 ;
        RECT 332.310 398.005 334.690 398.890 ;
        RECT 335.530 398.005 337.910 398.890 ;
        RECT 338.750 398.005 347.570 398.890 ;
        RECT 348.410 398.005 350.790 398.890 ;
        RECT 351.630 398.005 354.010 398.890 ;
        RECT 354.850 398.005 357.230 398.890 ;
        RECT 358.070 398.005 360.450 398.890 ;
        RECT 361.290 398.005 382.990 398.890 ;
        RECT 383.830 398.005 384.470 398.890 ;
        RECT 4.230 4.280 384.470 398.005 ;
        RECT 4.230 0.155 6.250 4.280 ;
        RECT 7.090 0.155 9.470 4.280 ;
        RECT 10.310 0.155 12.690 4.280 ;
        RECT 13.530 0.155 15.910 4.280 ;
        RECT 16.750 0.155 19.130 4.280 ;
        RECT 19.970 0.155 22.350 4.280 ;
        RECT 23.190 0.155 25.570 4.280 ;
        RECT 26.410 0.155 28.790 4.280 ;
        RECT 29.630 0.155 32.010 4.280 ;
        RECT 32.850 0.155 35.230 4.280 ;
        RECT 36.070 0.155 38.450 4.280 ;
        RECT 39.290 0.155 41.670 4.280 ;
        RECT 42.510 0.155 44.890 4.280 ;
        RECT 45.730 0.155 48.110 4.280 ;
        RECT 48.950 0.155 51.330 4.280 ;
        RECT 52.170 0.155 54.550 4.280 ;
        RECT 55.390 0.155 57.770 4.280 ;
        RECT 58.610 0.155 60.990 4.280 ;
        RECT 61.830 0.155 64.210 4.280 ;
        RECT 65.050 0.155 67.430 4.280 ;
        RECT 68.270 0.155 70.650 4.280 ;
        RECT 71.490 0.155 73.870 4.280 ;
        RECT 74.710 0.155 77.090 4.280 ;
        RECT 77.930 0.155 80.310 4.280 ;
        RECT 81.150 0.155 83.530 4.280 ;
        RECT 84.370 0.155 86.750 4.280 ;
        RECT 87.590 0.155 89.970 4.280 ;
        RECT 90.810 0.155 93.190 4.280 ;
        RECT 94.030 0.155 96.410 4.280 ;
        RECT 97.250 0.155 99.630 4.280 ;
        RECT 100.470 0.155 102.850 4.280 ;
        RECT 103.690 0.155 106.070 4.280 ;
        RECT 106.910 0.155 109.290 4.280 ;
        RECT 110.130 0.155 112.510 4.280 ;
        RECT 113.350 0.155 115.730 4.280 ;
        RECT 116.570 0.155 118.950 4.280 ;
        RECT 119.790 0.155 122.170 4.280 ;
        RECT 123.010 0.155 125.390 4.280 ;
        RECT 126.230 0.155 128.610 4.280 ;
        RECT 129.450 0.155 131.830 4.280 ;
        RECT 132.670 0.155 135.050 4.280 ;
        RECT 135.890 0.155 138.270 4.280 ;
        RECT 139.110 0.155 141.490 4.280 ;
        RECT 142.330 0.155 144.710 4.280 ;
        RECT 145.550 0.155 147.930 4.280 ;
        RECT 148.770 0.155 151.150 4.280 ;
        RECT 151.990 0.155 154.370 4.280 ;
        RECT 155.210 0.155 157.590 4.280 ;
        RECT 158.430 0.155 160.810 4.280 ;
        RECT 161.650 0.155 164.030 4.280 ;
        RECT 164.870 0.155 167.250 4.280 ;
        RECT 168.090 0.155 170.470 4.280 ;
        RECT 171.310 0.155 173.690 4.280 ;
        RECT 174.530 0.155 176.910 4.280 ;
        RECT 177.750 0.155 180.130 4.280 ;
        RECT 180.970 0.155 183.350 4.280 ;
        RECT 184.190 0.155 186.570 4.280 ;
        RECT 187.410 0.155 189.790 4.280 ;
        RECT 190.630 0.155 193.010 4.280 ;
        RECT 193.850 0.155 196.230 4.280 ;
        RECT 197.070 0.155 199.450 4.280 ;
        RECT 200.290 0.155 202.670 4.280 ;
        RECT 203.510 0.155 205.890 4.280 ;
        RECT 206.730 0.155 209.110 4.280 ;
        RECT 209.950 0.155 212.330 4.280 ;
        RECT 213.170 0.155 215.550 4.280 ;
        RECT 216.390 0.155 218.770 4.280 ;
        RECT 219.610 0.155 221.990 4.280 ;
        RECT 222.830 0.155 225.210 4.280 ;
        RECT 226.050 0.155 228.430 4.280 ;
        RECT 229.270 0.155 231.650 4.280 ;
        RECT 232.490 0.155 234.870 4.280 ;
        RECT 235.710 0.155 238.090 4.280 ;
        RECT 238.930 0.155 241.310 4.280 ;
        RECT 242.150 0.155 244.530 4.280 ;
        RECT 245.370 0.155 247.750 4.280 ;
        RECT 248.590 0.155 250.970 4.280 ;
        RECT 251.810 0.155 254.190 4.280 ;
        RECT 255.030 0.155 257.410 4.280 ;
        RECT 258.250 0.155 260.630 4.280 ;
        RECT 261.470 0.155 263.850 4.280 ;
        RECT 264.690 0.155 267.070 4.280 ;
        RECT 267.910 0.155 270.290 4.280 ;
        RECT 271.130 0.155 273.510 4.280 ;
        RECT 274.350 0.155 276.730 4.280 ;
        RECT 277.570 0.155 279.950 4.280 ;
        RECT 280.790 0.155 283.170 4.280 ;
        RECT 284.010 0.155 286.390 4.280 ;
        RECT 287.230 0.155 289.610 4.280 ;
        RECT 290.450 0.155 292.830 4.280 ;
        RECT 293.670 0.155 296.050 4.280 ;
        RECT 296.890 0.155 299.270 4.280 ;
        RECT 300.110 0.155 302.490 4.280 ;
        RECT 303.330 0.155 305.710 4.280 ;
        RECT 306.550 0.155 308.930 4.280 ;
        RECT 309.770 0.155 312.150 4.280 ;
        RECT 312.990 0.155 315.370 4.280 ;
        RECT 316.210 0.155 318.590 4.280 ;
        RECT 319.430 0.155 321.810 4.280 ;
        RECT 322.650 0.155 325.030 4.280 ;
        RECT 325.870 0.155 328.250 4.280 ;
        RECT 329.090 0.155 331.470 4.280 ;
        RECT 332.310 0.155 334.690 4.280 ;
        RECT 335.530 0.155 337.910 4.280 ;
        RECT 338.750 0.155 341.130 4.280 ;
        RECT 341.970 0.155 344.350 4.280 ;
        RECT 345.190 0.155 347.570 4.280 ;
        RECT 348.410 0.155 350.790 4.280 ;
        RECT 351.630 0.155 354.010 4.280 ;
        RECT 354.850 0.155 357.230 4.280 ;
        RECT 358.070 0.155 360.450 4.280 ;
        RECT 361.290 0.155 363.670 4.280 ;
        RECT 364.510 0.155 366.890 4.280 ;
        RECT 367.730 0.155 370.110 4.280 ;
        RECT 370.950 0.155 373.330 4.280 ;
        RECT 374.170 0.155 376.550 4.280 ;
        RECT 377.390 0.155 379.770 4.280 ;
        RECT 380.610 0.155 382.990 4.280 ;
        RECT 383.830 0.155 384.470 4.280 ;
      LAYER met3 ;
        RECT 3.950 390.640 387.165 391.505 ;
        RECT 3.950 388.640 387.565 390.640 ;
        RECT 3.950 387.240 387.165 388.640 ;
        RECT 3.950 385.240 387.565 387.240 ;
        RECT 4.400 383.840 387.165 385.240 ;
        RECT 3.950 381.840 387.565 383.840 ;
        RECT 4.400 380.440 387.165 381.840 ;
        RECT 3.950 378.440 387.565 380.440 ;
        RECT 4.400 377.040 387.165 378.440 ;
        RECT 3.950 375.040 387.565 377.040 ;
        RECT 4.400 373.640 387.165 375.040 ;
        RECT 3.950 371.640 387.565 373.640 ;
        RECT 4.400 370.240 387.165 371.640 ;
        RECT 3.950 368.240 387.565 370.240 ;
        RECT 3.950 366.840 387.165 368.240 ;
        RECT 3.950 364.840 387.565 366.840 ;
        RECT 3.950 363.440 387.165 364.840 ;
        RECT 3.950 361.440 387.565 363.440 ;
        RECT 3.950 360.040 387.165 361.440 ;
        RECT 3.950 358.040 387.565 360.040 ;
        RECT 3.950 356.640 387.165 358.040 ;
        RECT 3.950 354.640 387.565 356.640 ;
        RECT 3.950 353.240 387.165 354.640 ;
        RECT 3.950 351.240 387.565 353.240 ;
        RECT 3.950 349.840 387.165 351.240 ;
        RECT 3.950 347.840 387.565 349.840 ;
        RECT 3.950 346.440 387.165 347.840 ;
        RECT 3.950 344.440 387.565 346.440 ;
        RECT 3.950 343.040 387.165 344.440 ;
        RECT 3.950 341.040 387.565 343.040 ;
        RECT 3.950 339.640 387.165 341.040 ;
        RECT 3.950 337.640 387.565 339.640 ;
        RECT 3.950 336.240 387.165 337.640 ;
        RECT 3.950 334.240 387.565 336.240 ;
        RECT 3.950 332.840 387.165 334.240 ;
        RECT 3.950 330.840 387.565 332.840 ;
        RECT 3.950 329.440 387.165 330.840 ;
        RECT 3.950 327.440 387.565 329.440 ;
        RECT 4.400 326.040 387.165 327.440 ;
        RECT 3.950 324.040 387.565 326.040 ;
        RECT 4.400 322.640 387.165 324.040 ;
        RECT 3.950 320.640 387.565 322.640 ;
        RECT 4.400 319.240 387.165 320.640 ;
        RECT 3.950 317.240 387.565 319.240 ;
        RECT 4.400 315.840 387.165 317.240 ;
        RECT 3.950 313.840 387.565 315.840 ;
        RECT 4.400 312.440 387.165 313.840 ;
        RECT 3.950 310.440 387.565 312.440 ;
        RECT 4.400 309.040 387.165 310.440 ;
        RECT 3.950 307.040 387.565 309.040 ;
        RECT 4.400 305.640 387.165 307.040 ;
        RECT 3.950 303.640 387.565 305.640 ;
        RECT 4.400 302.240 387.165 303.640 ;
        RECT 3.950 300.240 387.565 302.240 ;
        RECT 4.400 298.840 387.165 300.240 ;
        RECT 3.950 296.840 387.565 298.840 ;
        RECT 4.400 295.440 387.165 296.840 ;
        RECT 3.950 293.440 387.565 295.440 ;
        RECT 4.400 292.040 387.165 293.440 ;
        RECT 3.950 290.040 387.565 292.040 ;
        RECT 4.400 288.640 387.165 290.040 ;
        RECT 3.950 286.640 387.565 288.640 ;
        RECT 4.400 285.240 387.165 286.640 ;
        RECT 3.950 283.240 387.565 285.240 ;
        RECT 4.400 281.840 387.165 283.240 ;
        RECT 3.950 279.840 387.565 281.840 ;
        RECT 4.400 278.440 387.165 279.840 ;
        RECT 3.950 276.440 387.565 278.440 ;
        RECT 4.400 275.040 387.165 276.440 ;
        RECT 3.950 273.040 387.565 275.040 ;
        RECT 4.400 271.640 387.165 273.040 ;
        RECT 3.950 269.640 387.565 271.640 ;
        RECT 4.400 268.240 387.165 269.640 ;
        RECT 3.950 266.240 387.565 268.240 ;
        RECT 4.400 264.840 387.165 266.240 ;
        RECT 3.950 262.840 387.565 264.840 ;
        RECT 4.400 261.440 387.165 262.840 ;
        RECT 3.950 259.440 387.565 261.440 ;
        RECT 4.400 258.040 387.165 259.440 ;
        RECT 3.950 256.040 387.565 258.040 ;
        RECT 4.400 254.640 387.165 256.040 ;
        RECT 3.950 252.640 387.565 254.640 ;
        RECT 4.400 251.240 387.165 252.640 ;
        RECT 3.950 249.240 387.565 251.240 ;
        RECT 4.400 247.840 387.165 249.240 ;
        RECT 3.950 245.840 387.565 247.840 ;
        RECT 4.400 244.440 387.165 245.840 ;
        RECT 3.950 242.440 387.565 244.440 ;
        RECT 4.400 241.040 387.165 242.440 ;
        RECT 3.950 239.040 387.565 241.040 ;
        RECT 4.400 237.640 387.165 239.040 ;
        RECT 3.950 235.640 387.565 237.640 ;
        RECT 4.400 234.240 387.165 235.640 ;
        RECT 3.950 232.240 387.565 234.240 ;
        RECT 4.400 230.840 387.165 232.240 ;
        RECT 3.950 228.840 387.565 230.840 ;
        RECT 4.400 227.440 387.165 228.840 ;
        RECT 3.950 225.440 387.565 227.440 ;
        RECT 4.400 224.040 387.165 225.440 ;
        RECT 3.950 222.040 387.565 224.040 ;
        RECT 4.400 220.640 387.165 222.040 ;
        RECT 3.950 218.640 387.565 220.640 ;
        RECT 4.400 217.240 387.165 218.640 ;
        RECT 3.950 215.240 387.565 217.240 ;
        RECT 4.400 213.840 387.165 215.240 ;
        RECT 3.950 211.840 387.565 213.840 ;
        RECT 4.400 210.440 387.165 211.840 ;
        RECT 3.950 208.440 387.565 210.440 ;
        RECT 4.400 207.040 387.165 208.440 ;
        RECT 3.950 205.040 387.565 207.040 ;
        RECT 4.400 203.640 387.165 205.040 ;
        RECT 3.950 201.640 387.565 203.640 ;
        RECT 4.400 200.240 387.165 201.640 ;
        RECT 3.950 198.240 387.565 200.240 ;
        RECT 4.400 196.840 387.165 198.240 ;
        RECT 3.950 194.840 387.565 196.840 ;
        RECT 4.400 193.440 387.165 194.840 ;
        RECT 3.950 191.440 387.565 193.440 ;
        RECT 4.400 190.040 387.165 191.440 ;
        RECT 3.950 188.040 387.565 190.040 ;
        RECT 4.400 186.640 387.165 188.040 ;
        RECT 3.950 184.640 387.565 186.640 ;
        RECT 4.400 183.240 387.165 184.640 ;
        RECT 3.950 181.240 387.565 183.240 ;
        RECT 4.400 179.840 387.165 181.240 ;
        RECT 3.950 177.840 387.565 179.840 ;
        RECT 4.400 176.440 387.165 177.840 ;
        RECT 3.950 174.440 387.565 176.440 ;
        RECT 4.400 173.040 387.165 174.440 ;
        RECT 3.950 171.040 387.565 173.040 ;
        RECT 4.400 169.640 387.165 171.040 ;
        RECT 3.950 167.640 387.565 169.640 ;
        RECT 4.400 166.240 387.165 167.640 ;
        RECT 3.950 164.240 387.565 166.240 ;
        RECT 4.400 162.840 387.165 164.240 ;
        RECT 3.950 160.840 387.565 162.840 ;
        RECT 4.400 159.440 387.165 160.840 ;
        RECT 3.950 157.440 387.565 159.440 ;
        RECT 4.400 156.040 387.165 157.440 ;
        RECT 3.950 154.040 387.565 156.040 ;
        RECT 4.400 152.640 387.165 154.040 ;
        RECT 3.950 150.640 387.565 152.640 ;
        RECT 4.400 149.240 387.165 150.640 ;
        RECT 3.950 147.240 387.565 149.240 ;
        RECT 4.400 145.840 387.165 147.240 ;
        RECT 3.950 143.840 387.565 145.840 ;
        RECT 4.400 142.440 387.165 143.840 ;
        RECT 3.950 140.440 387.565 142.440 ;
        RECT 4.400 139.040 387.165 140.440 ;
        RECT 3.950 137.040 387.565 139.040 ;
        RECT 4.400 135.640 387.165 137.040 ;
        RECT 3.950 133.640 387.565 135.640 ;
        RECT 4.400 132.240 387.165 133.640 ;
        RECT 3.950 130.240 387.565 132.240 ;
        RECT 4.400 128.840 387.165 130.240 ;
        RECT 3.950 126.840 387.565 128.840 ;
        RECT 4.400 125.440 387.165 126.840 ;
        RECT 3.950 123.440 387.565 125.440 ;
        RECT 4.400 122.040 387.165 123.440 ;
        RECT 3.950 120.040 387.565 122.040 ;
        RECT 4.400 118.640 387.165 120.040 ;
        RECT 3.950 116.640 387.565 118.640 ;
        RECT 4.400 115.240 387.165 116.640 ;
        RECT 3.950 113.240 387.565 115.240 ;
        RECT 4.400 111.840 387.165 113.240 ;
        RECT 3.950 109.840 387.565 111.840 ;
        RECT 4.400 108.440 387.165 109.840 ;
        RECT 3.950 106.440 387.565 108.440 ;
        RECT 4.400 105.040 387.165 106.440 ;
        RECT 3.950 103.040 387.565 105.040 ;
        RECT 4.400 101.640 387.165 103.040 ;
        RECT 3.950 99.640 387.565 101.640 ;
        RECT 4.400 98.240 387.165 99.640 ;
        RECT 3.950 96.240 387.565 98.240 ;
        RECT 4.400 94.840 387.165 96.240 ;
        RECT 3.950 92.840 387.565 94.840 ;
        RECT 4.400 91.440 387.165 92.840 ;
        RECT 3.950 89.440 387.565 91.440 ;
        RECT 4.400 88.040 387.165 89.440 ;
        RECT 3.950 86.040 387.565 88.040 ;
        RECT 4.400 84.640 387.165 86.040 ;
        RECT 3.950 82.640 387.565 84.640 ;
        RECT 4.400 81.240 387.165 82.640 ;
        RECT 3.950 79.240 387.565 81.240 ;
        RECT 4.400 77.840 387.165 79.240 ;
        RECT 3.950 75.840 387.565 77.840 ;
        RECT 4.400 74.440 387.165 75.840 ;
        RECT 3.950 72.440 387.565 74.440 ;
        RECT 4.400 71.040 387.165 72.440 ;
        RECT 3.950 69.040 387.565 71.040 ;
        RECT 4.400 67.640 387.165 69.040 ;
        RECT 3.950 65.640 387.565 67.640 ;
        RECT 4.400 64.240 387.165 65.640 ;
        RECT 3.950 62.240 387.565 64.240 ;
        RECT 4.400 60.840 387.165 62.240 ;
        RECT 3.950 58.840 387.565 60.840 ;
        RECT 4.400 57.440 387.165 58.840 ;
        RECT 3.950 55.440 387.565 57.440 ;
        RECT 4.400 54.040 387.165 55.440 ;
        RECT 3.950 52.040 387.565 54.040 ;
        RECT 4.400 50.640 387.165 52.040 ;
        RECT 3.950 48.640 387.565 50.640 ;
        RECT 4.400 47.240 387.165 48.640 ;
        RECT 3.950 45.240 387.565 47.240 ;
        RECT 4.400 43.840 387.165 45.240 ;
        RECT 3.950 41.840 387.565 43.840 ;
        RECT 4.400 40.440 387.165 41.840 ;
        RECT 3.950 38.440 387.565 40.440 ;
        RECT 4.400 37.040 387.165 38.440 ;
        RECT 3.950 35.040 387.565 37.040 ;
        RECT 4.400 33.640 387.165 35.040 ;
        RECT 3.950 31.640 387.565 33.640 ;
        RECT 4.400 30.240 387.165 31.640 ;
        RECT 3.950 28.240 387.565 30.240 ;
        RECT 4.400 26.840 387.165 28.240 ;
        RECT 3.950 24.840 387.565 26.840 ;
        RECT 4.400 23.440 387.165 24.840 ;
        RECT 3.950 21.440 387.565 23.440 ;
        RECT 4.400 20.040 387.165 21.440 ;
        RECT 3.950 18.040 387.565 20.040 ;
        RECT 3.950 16.640 387.165 18.040 ;
        RECT 3.950 14.640 387.565 16.640 ;
        RECT 3.950 13.240 387.165 14.640 ;
        RECT 3.950 11.240 387.565 13.240 ;
        RECT 3.950 9.840 387.165 11.240 ;
        RECT 3.950 7.840 387.565 9.840 ;
        RECT 3.950 6.440 387.165 7.840 ;
        RECT 3.950 4.440 387.565 6.440 ;
        RECT 3.950 3.040 387.165 4.440 ;
        RECT 3.950 1.040 387.565 3.040 ;
        RECT 3.950 0.175 387.165 1.040 ;
      LAYER met4 ;
        RECT 3.975 102.175 20.640 300.385 ;
        RECT 23.040 102.175 23.940 300.385 ;
        RECT 26.340 102.175 174.240 300.385 ;
        RECT 176.640 102.175 177.540 300.385 ;
        RECT 179.940 102.175 327.840 300.385 ;
        RECT 330.240 102.175 331.140 300.385 ;
        RECT 333.540 102.175 343.785 300.385 ;
  END
END neuron_core
END LIBRARY

